VERSION 5.7 ;
  NOWIREEXTENSIONATPIN ON ;
  DIVIDERCHAR "/" ;
  BUSBITCHARS "[]" ;
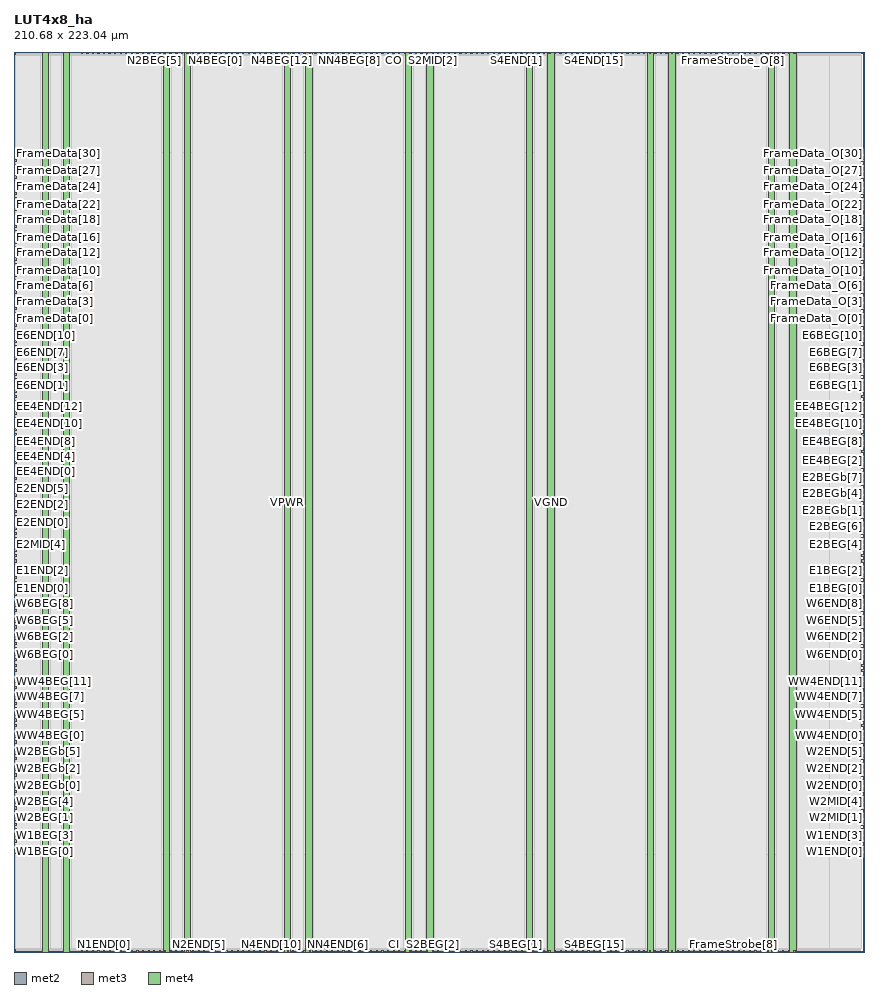
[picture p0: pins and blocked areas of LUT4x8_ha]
MACRO LUT4x8_ha
  CLASS BLOCK ;
  FOREIGN LUT4x8_ha ;
  ORIGIN 0.000 0.000 ;
  SIZE 210.680 BY 223.040 ;
  PIN CI
    DIRECTION INPUT ;
    USE SIGNAL ;
    ANTENNAGATEAREA 0.499500 ;
    PORT
      LAYER met2 ;
        RECT 93.930 0.000 94.210 0.280 ;
    END
  END CI
  PIN CO
    DIRECTION OUTPUT ;
    USE SIGNAL ;
    ANTENNADIFFAREA 0.702900 ;
    PORT
      LAYER met2 ;
        RECT 93.930 222.760 94.210 223.040 ;
    END
  END CO
  PIN E1BEG[0]
    DIRECTION OUTPUT ;
    USE SIGNAL ;
    ANTENNADIFFAREA 0.702900 ;
    PORT
      LAYER met3 ;
        RECT 210.080 89.800 210.680 90.400 ;
    END
  END E1BEG[0]
  PIN E1BEG[1]
    DIRECTION OUTPUT ;
    USE SIGNAL ;
    ANTENNADIFFAREA 0.702900 ;
    PORT
      LAYER met3 ;
        RECT 210.080 91.160 210.680 91.760 ;
    END
  END E1BEG[1]
  PIN E1BEG[2]
    DIRECTION OUTPUT ;
    USE SIGNAL ;
    ANTENNADIFFAREA 0.702900 ;
    PORT
      LAYER met3 ;
        RECT 210.080 92.520 210.680 93.120 ;
    END
  END E1BEG[2]
  PIN E1BEG[3]
    DIRECTION OUTPUT ;
    USE SIGNAL ;
    ANTENNADIFFAREA 0.702900 ;
    PORT
      LAYER met3 ;
        RECT 210.080 93.880 210.680 94.480 ;
    END
  END E1BEG[3]
  PIN E1END[0]
    DIRECTION INPUT ;
    USE SIGNAL ;
    ANTENNAGATEAREA 2.912100 ;
    ANTENNADIFFAREA 1.304100 ;
    PORT
      LAYER met3 ;
        RECT 0.000 89.800 0.600 90.400 ;
    END
  END E1END[0]
  PIN E1END[1]
    DIRECTION INPUT ;
    USE SIGNAL ;
    ANTENNAGATEAREA 1.431000 ;
    PORT
      LAYER met3 ;
        RECT 0.000 91.160 0.600 91.760 ;
    END
  END E1END[1]
  PIN E1END[2]
    DIRECTION INPUT ;
    USE SIGNAL ;
    ANTENNAGATEAREA 1.749000 ;
    PORT
      LAYER met3 ;
        RECT 0.000 92.520 0.600 93.120 ;
    END
  END E1END[2]
  PIN E1END[3]
    DIRECTION INPUT ;
    USE SIGNAL ;
    ANTENNAGATEAREA 2.618400 ;
    ANTENNADIFFAREA 0.869400 ;
    PORT
      LAYER met3 ;
        RECT 0.000 93.880 0.600 94.480 ;
    END
  END E1END[3]
  PIN E2BEG[0]
    DIRECTION OUTPUT ;
    USE SIGNAL ;
    ANTENNADIFFAREA 0.702900 ;
    PORT
      LAYER met3 ;
        RECT 210.080 95.240 210.680 95.840 ;
    END
  END E2BEG[0]
  PIN E2BEG[1]
    DIRECTION OUTPUT ;
    USE SIGNAL ;
    ANTENNADIFFAREA 0.702900 ;
    PORT
      LAYER met3 ;
        RECT 210.080 96.600 210.680 97.200 ;
    END
  END E2BEG[1]
  PIN E2BEG[2]
    DIRECTION OUTPUT ;
    USE SIGNAL ;
    ANTENNADIFFAREA 0.702900 ;
    PORT
      LAYER met3 ;
        RECT 210.080 97.960 210.680 98.560 ;
    END
  END E2BEG[2]
  PIN E2BEG[3]
    DIRECTION OUTPUT ;
    USE SIGNAL ;
    ANTENNADIFFAREA 0.702900 ;
    PORT
      LAYER met3 ;
        RECT 210.080 99.320 210.680 99.920 ;
    END
  END E2BEG[3]
  PIN E2BEG[4]
    DIRECTION OUTPUT ;
    USE SIGNAL ;
    ANTENNADIFFAREA 0.702900 ;
    PORT
      LAYER met3 ;
        RECT 210.080 100.680 210.680 101.280 ;
    END
  END E2BEG[4]
  PIN E2BEG[5]
    DIRECTION OUTPUT ;
    USE SIGNAL ;
    ANTENNADIFFAREA 0.702900 ;
    PORT
      LAYER met3 ;
        RECT 210.080 102.040 210.680 102.640 ;
    END
  END E2BEG[5]
  PIN E2BEG[6]
    DIRECTION OUTPUT ;
    USE SIGNAL ;
    ANTENNADIFFAREA 0.702900 ;
    PORT
      LAYER met3 ;
        RECT 210.080 103.400 210.680 104.000 ;
    END
  END E2BEG[6]
  PIN E2BEG[7]
    DIRECTION OUTPUT ;
    USE SIGNAL ;
    ANTENNADIFFAREA 0.702900 ;
    PORT
      LAYER met3 ;
        RECT 210.080 104.760 210.680 105.360 ;
    END
  END E2BEG[7]
  PIN E2BEGb[0]
    DIRECTION OUTPUT ;
    USE SIGNAL ;
    ANTENNADIFFAREA 0.702900 ;
    PORT
      LAYER met3 ;
        RECT 210.080 106.120 210.680 106.720 ;
    END
  END E2BEGb[0]
  PIN E2BEGb[1]
    DIRECTION OUTPUT ;
    USE SIGNAL ;
    ANTENNADIFFAREA 0.702900 ;
    PORT
      LAYER met3 ;
        RECT 210.080 107.480 210.680 108.080 ;
    END
  END E2BEGb[1]
  PIN E2BEGb[2]
    DIRECTION OUTPUT ;
    USE SIGNAL ;
    ANTENNADIFFAREA 0.702900 ;
    PORT
      LAYER met3 ;
        RECT 210.080 108.840 210.680 109.440 ;
    END
  END E2BEGb[2]
  PIN E2BEGb[3]
    DIRECTION OUTPUT ;
    USE SIGNAL ;
    ANTENNADIFFAREA 0.702900 ;
    PORT
      LAYER met3 ;
        RECT 210.080 110.200 210.680 110.800 ;
    END
  END E2BEGb[3]
  PIN E2BEGb[4]
    DIRECTION OUTPUT ;
    USE SIGNAL ;
    ANTENNADIFFAREA 0.702900 ;
    PORT
      LAYER met3 ;
        RECT 210.080 111.560 210.680 112.160 ;
    END
  END E2BEGb[4]
  PIN E2BEGb[5]
    DIRECTION OUTPUT ;
    USE SIGNAL ;
    ANTENNADIFFAREA 0.702900 ;
    PORT
      LAYER met3 ;
        RECT 210.080 112.920 210.680 113.520 ;
    END
  END E2BEGb[5]
  PIN E2BEGb[6]
    DIRECTION OUTPUT ;
    USE SIGNAL ;
    ANTENNADIFFAREA 0.702900 ;
    PORT
      LAYER met3 ;
        RECT 210.080 114.280 210.680 114.880 ;
    END
  END E2BEGb[6]
  PIN E2BEGb[7]
    DIRECTION OUTPUT ;
    USE SIGNAL ;
    ANTENNADIFFAREA 0.702900 ;
    PORT
      LAYER met3 ;
        RECT 210.080 115.640 210.680 116.240 ;
    END
  END E2BEGb[7]
  PIN E2END[0]
    DIRECTION INPUT ;
    USE SIGNAL ;
    ANTENNAGATEAREA 0.636000 ;
    PORT
      LAYER met3 ;
        RECT 0.000 106.120 0.600 106.720 ;
    END
  END E2END[0]
  PIN E2END[1]
    DIRECTION INPUT ;
    USE SIGNAL ;
    ANTENNAGATEAREA 1.070700 ;
    ANTENNADIFFAREA 0.434700 ;
    PORT
      LAYER met3 ;
        RECT 0.000 107.480 0.600 108.080 ;
    END
  END E2END[1]
  PIN E2END[2]
    DIRECTION INPUT ;
    USE SIGNAL ;
    ANTENNAGATEAREA 1.113000 ;
    PORT
      LAYER met3 ;
        RECT 0.000 108.840 0.600 109.440 ;
    END
  END E2END[2]
  PIN E2END[3]
    DIRECTION INPUT ;
    USE SIGNAL ;
    ANTENNAGATEAREA 1.113000 ;
    PORT
      LAYER met3 ;
        RECT 0.000 110.200 0.600 110.800 ;
    END
  END E2END[3]
  PIN E2END[4]
    DIRECTION INPUT ;
    USE SIGNAL ;
    ANTENNAGATEAREA 0.795000 ;
    PORT
      LAYER met3 ;
        RECT 0.000 111.560 0.600 112.160 ;
    END
  END E2END[4]
  PIN E2END[5]
    DIRECTION INPUT ;
    USE SIGNAL ;
    ANTENNAGATEAREA 0.954000 ;
    PORT
      LAYER met3 ;
        RECT 0.000 112.920 0.600 113.520 ;
    END
  END E2END[5]
  PIN E2END[6]
    DIRECTION INPUT ;
    USE SIGNAL ;
    ANTENNAGATEAREA 0.954000 ;
    PORT
      LAYER met3 ;
        RECT 0.000 114.280 0.600 114.880 ;
    END
  END E2END[6]
  PIN E2END[7]
    DIRECTION INPUT ;
    USE SIGNAL ;
    ANTENNAGATEAREA 0.795000 ;
    PORT
      LAYER met3 ;
        RECT 0.000 115.640 0.600 116.240 ;
    END
  END E2END[7]
  PIN E2MID[0]
    DIRECTION INPUT ;
    USE SIGNAL ;
    ANTENNAGATEAREA 0.636000 ;
    PORT
      LAYER met3 ;
        RECT 0.000 95.240 0.600 95.840 ;
    END
  END E2MID[0]
  PIN E2MID[1]
    DIRECTION INPUT ;
    USE SIGNAL ;
    ANTENNAGATEAREA 0.795000 ;
    PORT
      LAYER met3 ;
        RECT 0.000 96.600 0.600 97.200 ;
    END
  END E2MID[1]
  PIN E2MID[2]
    DIRECTION INPUT ;
    USE SIGNAL ;
    ANTENNAGATEAREA 2.374800 ;
    ANTENNADIFFAREA 1.738800 ;
    PORT
      LAYER met3 ;
        RECT 0.000 97.960 0.600 98.560 ;
    END
  END E2MID[2]
  PIN E2MID[3]
    DIRECTION INPUT ;
    USE SIGNAL ;
    ANTENNAGATEAREA 1.664400 ;
    ANTENNADIFFAREA 0.869400 ;
    PORT
      LAYER met3 ;
        RECT 0.000 99.320 0.600 99.920 ;
    END
  END E2MID[3]
  PIN E2MID[4]
    DIRECTION INPUT ;
    USE SIGNAL ;
    ANTENNAGATEAREA 1.196700 ;
    ANTENNADIFFAREA 0.434700 ;
    PORT
      LAYER met3 ;
        RECT 0.000 100.680 0.600 101.280 ;
    END
  END E2MID[4]
  PIN E2MID[5]
    DIRECTION INPUT ;
    USE SIGNAL ;
    ANTENNAGATEAREA 0.795000 ;
    PORT
      LAYER met3 ;
        RECT 0.000 102.040 0.600 102.640 ;
    END
  END E2MID[5]
  PIN E2MID[6]
    DIRECTION INPUT ;
    USE SIGNAL ;
    ANTENNAGATEAREA 1.940100 ;
    ANTENNADIFFAREA 1.304100 ;
    PORT
      LAYER met3 ;
        RECT 0.000 103.400 0.600 104.000 ;
    END
  END E2MID[6]
  PIN E2MID[7]
    DIRECTION INPUT ;
    USE SIGNAL ;
    ANTENNAGATEAREA 0.795000 ;
    PORT
      LAYER met3 ;
        RECT 0.000 104.760 0.600 105.360 ;
    END
  END E2MID[7]
  PIN E6BEG[0]
    DIRECTION OUTPUT ;
    USE SIGNAL ;
    ANTENNADIFFAREA 0.702900 ;
    PORT
      LAYER met3 ;
        RECT 210.080 138.760 210.680 139.360 ;
    END
  END E6BEG[0]
  PIN E6BEG[10]
    DIRECTION OUTPUT ;
    USE SIGNAL ;
    ANTENNADIFFAREA 0.702900 ;
    PORT
      LAYER met3 ;
        RECT 210.080 152.360 210.680 152.960 ;
    END
  END E6BEG[10]
  PIN E6BEG[11]
    DIRECTION OUTPUT ;
    USE SIGNAL ;
    ANTENNADIFFAREA 0.702900 ;
    PORT
      LAYER met3 ;
        RECT 210.080 153.720 210.680 154.320 ;
    END
  END E6BEG[11]
  PIN E6BEG[1]
    DIRECTION OUTPUT ;
    USE SIGNAL ;
    ANTENNADIFFAREA 0.702900 ;
    PORT
      LAYER met3 ;
        RECT 210.080 140.120 210.680 140.720 ;
    END
  END E6BEG[1]
  PIN E6BEG[2]
    DIRECTION OUTPUT ;
    USE SIGNAL ;
    ANTENNADIFFAREA 0.702900 ;
    PORT
      LAYER met3 ;
        RECT 210.080 141.480 210.680 142.080 ;
    END
  END E6BEG[2]
  PIN E6BEG[3]
    DIRECTION OUTPUT ;
    USE SIGNAL ;
    ANTENNADIFFAREA 0.702900 ;
    PORT
      LAYER met3 ;
        RECT 210.080 142.840 210.680 143.440 ;
    END
  END E6BEG[3]
  PIN E6BEG[4]
    DIRECTION OUTPUT ;
    USE SIGNAL ;
    ANTENNADIFFAREA 0.702900 ;
    PORT
      LAYER met3 ;
        RECT 210.080 144.200 210.680 144.800 ;
    END
  END E6BEG[4]
  PIN E6BEG[5]
    DIRECTION OUTPUT ;
    USE SIGNAL ;
    ANTENNADIFFAREA 0.702900 ;
    PORT
      LAYER met3 ;
        RECT 210.080 145.560 210.680 146.160 ;
    END
  END E6BEG[5]
  PIN E6BEG[6]
    DIRECTION OUTPUT ;
    USE SIGNAL ;
    ANTENNADIFFAREA 0.702900 ;
    PORT
      LAYER met3 ;
        RECT 210.080 146.920 210.680 147.520 ;
    END
  END E6BEG[6]
  PIN E6BEG[7]
    DIRECTION OUTPUT ;
    USE SIGNAL ;
    ANTENNADIFFAREA 0.702900 ;
    PORT
      LAYER met3 ;
        RECT 210.080 148.280 210.680 148.880 ;
    END
  END E6BEG[7]
  PIN E6BEG[8]
    DIRECTION OUTPUT ;
    USE SIGNAL ;
    ANTENNADIFFAREA 0.702900 ;
    PORT
      LAYER met3 ;
        RECT 210.080 149.640 210.680 150.240 ;
    END
  END E6BEG[8]
  PIN E6BEG[9]
    DIRECTION OUTPUT ;
    USE SIGNAL ;
    ANTENNADIFFAREA 0.702900 ;
    PORT
      LAYER met3 ;
        RECT 210.080 151.000 210.680 151.600 ;
    END
  END E6BEG[9]
  PIN E6END[0]
    DIRECTION INPUT ;
    USE SIGNAL ;
    ANTENNAGATEAREA 1.908000 ;
    PORT
      LAYER met3 ;
        RECT 0.000 138.760 0.600 139.360 ;
    END
  END E6END[0]
  PIN E6END[10]
    DIRECTION INPUT ;
    USE SIGNAL ;
    ANTENNAGATEAREA 0.159000 ;
    PORT
      LAYER met3 ;
        RECT 0.000 152.360 0.600 152.960 ;
    END
  END E6END[10]
  PIN E6END[11]
    DIRECTION INPUT ;
    USE SIGNAL ;
    ANTENNAGATEAREA 0.159000 ;
    PORT
      LAYER met3 ;
        RECT 0.000 153.720 0.600 154.320 ;
    END
  END E6END[11]
  PIN E6END[1]
    DIRECTION INPUT ;
    USE SIGNAL ;
    ANTENNAGATEAREA 3.646800 ;
    ANTENNADIFFAREA 1.738800 ;
    PORT
      LAYER met3 ;
        RECT 0.000 140.120 0.600 140.720 ;
    END
  END E6END[1]
  PIN E6END[2]
    DIRECTION INPUT ;
    USE SIGNAL ;
    ANTENNAGATEAREA 0.159000 ;
    PORT
      LAYER met3 ;
        RECT 0.000 141.480 0.600 142.080 ;
    END
  END E6END[2]
  PIN E6END[3]
    DIRECTION INPUT ;
    USE SIGNAL ;
    ANTENNAGATEAREA 0.159000 ;
    PORT
      LAYER met3 ;
        RECT 0.000 142.840 0.600 143.440 ;
    END
  END E6END[3]
  PIN E6END[4]
    DIRECTION INPUT ;
    USE SIGNAL ;
    ANTENNAGATEAREA 0.159000 ;
    PORT
      LAYER met3 ;
        RECT 0.000 144.200 0.600 144.800 ;
    END
  END E6END[4]
  PIN E6END[5]
    DIRECTION INPUT ;
    USE SIGNAL ;
    ANTENNAGATEAREA 0.159000 ;
    PORT
      LAYER met3 ;
        RECT 0.000 145.560 0.600 146.160 ;
    END
  END E6END[5]
  PIN E6END[6]
    DIRECTION INPUT ;
    USE SIGNAL ;
    ANTENNAGATEAREA 0.159000 ;
    PORT
      LAYER met3 ;
        RECT 0.000 146.920 0.600 147.520 ;
    END
  END E6END[6]
  PIN E6END[7]
    DIRECTION INPUT ;
    USE SIGNAL ;
    ANTENNAGATEAREA 0.159000 ;
    PORT
      LAYER met3 ;
        RECT 0.000 148.280 0.600 148.880 ;
    END
  END E6END[7]
  PIN E6END[8]
    DIRECTION INPUT ;
    USE SIGNAL ;
    ANTENNAGATEAREA 0.159000 ;
    PORT
      LAYER met3 ;
        RECT 0.000 149.640 0.600 150.240 ;
    END
  END E6END[8]
  PIN E6END[9]
    DIRECTION INPUT ;
    USE SIGNAL ;
    ANTENNAGATEAREA 0.159000 ;
    PORT
      LAYER met3 ;
        RECT 0.000 151.000 0.600 151.600 ;
    END
  END E6END[9]
  PIN EE4BEG[0]
    DIRECTION OUTPUT ;
    USE SIGNAL ;
    ANTENNADIFFAREA 0.702900 ;
    PORT
      LAYER met3 ;
        RECT 210.080 117.000 210.680 117.600 ;
    END
  END EE4BEG[0]
  PIN EE4BEG[10]
    DIRECTION OUTPUT ;
    USE SIGNAL ;
    ANTENNADIFFAREA 0.702900 ;
    PORT
      LAYER met3 ;
        RECT 210.080 130.600 210.680 131.200 ;
    END
  END EE4BEG[10]
  PIN EE4BEG[11]
    DIRECTION OUTPUT ;
    USE SIGNAL ;
    ANTENNADIFFAREA 0.702900 ;
    PORT
      LAYER met3 ;
        RECT 210.080 131.960 210.680 132.560 ;
    END
  END EE4BEG[11]
  PIN EE4BEG[12]
    DIRECTION OUTPUT ;
    USE SIGNAL ;
    ANTENNADIFFAREA 0.702900 ;
    PORT
      LAYER met3 ;
        RECT 210.080 133.320 210.680 133.920 ;
    END
  END EE4BEG[12]
  PIN EE4BEG[13]
    DIRECTION OUTPUT ;
    USE SIGNAL ;
    ANTENNADIFFAREA 0.702900 ;
    PORT
      LAYER met3 ;
        RECT 210.080 134.680 210.680 135.280 ;
    END
  END EE4BEG[13]
  PIN EE4BEG[14]
    DIRECTION OUTPUT ;
    USE SIGNAL ;
    ANTENNADIFFAREA 0.702900 ;
    PORT
      LAYER met3 ;
        RECT 210.080 136.040 210.680 136.640 ;
    END
  END EE4BEG[14]
  PIN EE4BEG[15]
    DIRECTION OUTPUT ;
    USE SIGNAL ;
    ANTENNADIFFAREA 0.702900 ;
    PORT
      LAYER met3 ;
        RECT 210.080 137.400 210.680 138.000 ;
    END
  END EE4BEG[15]
  PIN EE4BEG[1]
    DIRECTION OUTPUT ;
    USE SIGNAL ;
    ANTENNADIFFAREA 0.702900 ;
    PORT
      LAYER met3 ;
        RECT 210.080 118.360 210.680 118.960 ;
    END
  END EE4BEG[1]
  PIN EE4BEG[2]
    DIRECTION OUTPUT ;
    USE SIGNAL ;
    ANTENNADIFFAREA 0.702900 ;
    PORT
      LAYER met3 ;
        RECT 210.080 119.720 210.680 120.320 ;
    END
  END EE4BEG[2]
  PIN EE4BEG[3]
    DIRECTION OUTPUT ;
    USE SIGNAL ;
    ANTENNADIFFAREA 0.702900 ;
    PORT
      LAYER met3 ;
        RECT 210.080 121.080 210.680 121.680 ;
    END
  END EE4BEG[3]
  PIN EE4BEG[4]
    DIRECTION OUTPUT ;
    USE SIGNAL ;
    ANTENNADIFFAREA 0.702900 ;
    PORT
      LAYER met3 ;
        RECT 210.080 122.440 210.680 123.040 ;
    END
  END EE4BEG[4]
  PIN EE4BEG[5]
    DIRECTION OUTPUT ;
    USE SIGNAL ;
    ANTENNADIFFAREA 0.702900 ;
    PORT
      LAYER met3 ;
        RECT 210.080 123.800 210.680 124.400 ;
    END
  END EE4BEG[5]
  PIN EE4BEG[6]
    DIRECTION OUTPUT ;
    USE SIGNAL ;
    ANTENNADIFFAREA 0.702900 ;
    PORT
      LAYER met3 ;
        RECT 210.080 125.160 210.680 125.760 ;
    END
  END EE4BEG[6]
  PIN EE4BEG[7]
    DIRECTION OUTPUT ;
    USE SIGNAL ;
    ANTENNADIFFAREA 0.702900 ;
    PORT
      LAYER met3 ;
        RECT 210.080 126.520 210.680 127.120 ;
    END
  END EE4BEG[7]
  PIN EE4BEG[8]
    DIRECTION OUTPUT ;
    USE SIGNAL ;
    ANTENNADIFFAREA 0.702900 ;
    PORT
      LAYER met3 ;
        RECT 210.080 127.880 210.680 128.480 ;
    END
  END EE4BEG[8]
  PIN EE4BEG[9]
    DIRECTION OUTPUT ;
    USE SIGNAL ;
    ANTENNADIFFAREA 0.702900 ;
    PORT
      LAYER met3 ;
        RECT 210.080 129.240 210.680 129.840 ;
    END
  END EE4BEG[9]
  PIN EE4END[0]
    DIRECTION INPUT ;
    USE SIGNAL ;
    ANTENNAGATEAREA 0.911700 ;
    ANTENNADIFFAREA 0.434700 ;
    PORT
      LAYER met3 ;
        RECT 0.000 117.000 0.600 117.600 ;
    END
  END EE4END[0]
  PIN EE4END[10]
    DIRECTION INPUT ;
    USE SIGNAL ;
    ANTENNAGATEAREA 0.159000 ;
    PORT
      LAYER met3 ;
        RECT 0.000 130.600 0.600 131.200 ;
    END
  END EE4END[10]
  PIN EE4END[11]
    DIRECTION INPUT ;
    USE SIGNAL ;
    ANTENNAGATEAREA 0.159000 ;
    PORT
      LAYER met3 ;
        RECT 0.000 131.960 0.600 132.560 ;
    END
  END EE4END[11]
  PIN EE4END[12]
    DIRECTION INPUT ;
    USE SIGNAL ;
    ANTENNAGATEAREA 0.159000 ;
    PORT
      LAYER met3 ;
        RECT 0.000 133.320 0.600 133.920 ;
    END
  END EE4END[12]
  PIN EE4END[13]
    DIRECTION INPUT ;
    USE SIGNAL ;
    ANTENNAGATEAREA 0.159000 ;
    PORT
      LAYER met3 ;
        RECT 0.000 134.680 0.600 135.280 ;
    END
  END EE4END[13]
  PIN EE4END[14]
    DIRECTION INPUT ;
    USE SIGNAL ;
    ANTENNAGATEAREA 0.159000 ;
    PORT
      LAYER met3 ;
        RECT 0.000 136.040 0.600 136.640 ;
    END
  END EE4END[14]
  PIN EE4END[15]
    DIRECTION INPUT ;
    USE SIGNAL ;
    ANTENNAGATEAREA 0.159000 ;
    PORT
      LAYER met3 ;
        RECT 0.000 137.400 0.600 138.000 ;
    END
  END EE4END[15]
  PIN EE4END[1]
    DIRECTION INPUT ;
    USE SIGNAL ;
    ANTENNAGATEAREA 1.346400 ;
    ANTENNADIFFAREA 0.869400 ;
    PORT
      LAYER met3 ;
        RECT 0.000 118.360 0.600 118.960 ;
    END
  END EE4END[1]
  PIN EE4END[2]
    DIRECTION INPUT ;
    USE SIGNAL ;
    ANTENNAGATEAREA 1.346400 ;
    ANTENNADIFFAREA 0.869400 ;
    PORT
      LAYER met3 ;
        RECT 0.000 119.720 0.600 120.320 ;
    END
  END EE4END[2]
  PIN EE4END[3]
    DIRECTION INPUT ;
    USE SIGNAL ;
    ANTENNAGATEAREA 0.477000 ;
    PORT
      LAYER met3 ;
        RECT 0.000 121.080 0.600 121.680 ;
    END
  END EE4END[3]
  PIN EE4END[4]
    DIRECTION INPUT ;
    USE SIGNAL ;
    ANTENNAGATEAREA 0.159000 ;
    PORT
      LAYER met3 ;
        RECT 0.000 122.440 0.600 123.040 ;
    END
  END EE4END[4]
  PIN EE4END[5]
    DIRECTION INPUT ;
    USE SIGNAL ;
    ANTENNAGATEAREA 0.159000 ;
    PORT
      LAYER met3 ;
        RECT 0.000 123.800 0.600 124.400 ;
    END
  END EE4END[5]
  PIN EE4END[6]
    DIRECTION INPUT ;
    USE SIGNAL ;
    ANTENNAGATEAREA 0.159000 ;
    PORT
      LAYER met3 ;
        RECT 0.000 125.160 0.600 125.760 ;
    END
  END EE4END[6]
  PIN EE4END[7]
    DIRECTION INPUT ;
    USE SIGNAL ;
    ANTENNAGATEAREA 0.159000 ;
    PORT
      LAYER met3 ;
        RECT 0.000 126.520 0.600 127.120 ;
    END
  END EE4END[7]
  PIN EE4END[8]
    DIRECTION INPUT ;
    USE SIGNAL ;
    ANTENNAGATEAREA 0.159000 ;
    PORT
      LAYER met3 ;
        RECT 0.000 127.880 0.600 128.480 ;
    END
  END EE4END[8]
  PIN EE4END[9]
    DIRECTION INPUT ;
    USE SIGNAL ;
    ANTENNAGATEAREA 0.159000 ;
    PORT
      LAYER met3 ;
        RECT 0.000 129.240 0.600 129.840 ;
    END
  END EE4END[9]
  PIN FrameData[0]
    DIRECTION INPUT ;
    USE SIGNAL ;
    ANTENNAGATEAREA 4.918800 ;
    ANTENNADIFFAREA 1.738800 ;
    PORT
      LAYER met3 ;
        RECT 0.000 155.080 0.600 155.680 ;
    END
  END FrameData[0]
  PIN FrameData[10]
    DIRECTION INPUT ;
    USE SIGNAL ;
    ANTENNAGATEAREA 3.180000 ;
    PORT
      LAYER met3 ;
        RECT 0.000 168.680 0.600 169.280 ;
    END
  END FrameData[10]
  PIN FrameData[11]
    DIRECTION INPUT ;
    USE SIGNAL ;
    ANTENNAGATEAREA 3.180000 ;
    PORT
      LAYER met3 ;
        RECT 0.000 170.040 0.600 170.640 ;
    END
  END FrameData[11]
  PIN FrameData[12]
    DIRECTION INPUT ;
    USE SIGNAL ;
    ANTENNAGATEAREA 3.180000 ;
    PORT
      LAYER met3 ;
        RECT 0.000 171.400 0.600 172.000 ;
    END
  END FrameData[12]
  PIN FrameData[13]
    DIRECTION INPUT ;
    USE SIGNAL ;
    ANTENNAGATEAREA 3.180000 ;
    PORT
      LAYER met3 ;
        RECT 0.000 172.760 0.600 173.360 ;
    END
  END FrameData[13]
  PIN FrameData[14]
    DIRECTION INPUT ;
    USE SIGNAL ;
    ANTENNAGATEAREA 3.180000 ;
    PORT
      LAYER met3 ;
        RECT 0.000 174.120 0.600 174.720 ;
    END
  END FrameData[14]
  PIN FrameData[15]
    DIRECTION INPUT ;
    USE SIGNAL ;
    ANTENNAGATEAREA 3.180000 ;
    PORT
      LAYER met3 ;
        RECT 0.000 175.480 0.600 176.080 ;
    END
  END FrameData[15]
  PIN FrameData[16]
    DIRECTION INPUT ;
    USE SIGNAL ;
    ANTENNAGATEAREA 3.180000 ;
    PORT
      LAYER met3 ;
        RECT 0.000 176.840 0.600 177.440 ;
    END
  END FrameData[16]
  PIN FrameData[17]
    DIRECTION INPUT ;
    USE SIGNAL ;
    ANTENNAGATEAREA 3.180000 ;
    PORT
      LAYER met3 ;
        RECT 0.000 178.200 0.600 178.800 ;
    END
  END FrameData[17]
  PIN FrameData[18]
    DIRECTION INPUT ;
    USE SIGNAL ;
    ANTENNAGATEAREA 3.180000 ;
    PORT
      LAYER met3 ;
        RECT 0.000 179.560 0.600 180.160 ;
    END
  END FrameData[18]
  PIN FrameData[19]
    DIRECTION INPUT ;
    USE SIGNAL ;
    ANTENNAGATEAREA 3.180000 ;
    PORT
      LAYER met3 ;
        RECT 0.000 180.920 0.600 181.520 ;
    END
  END FrameData[19]
  PIN FrameData[1]
    DIRECTION INPUT ;
    USE SIGNAL ;
    ANTENNAGATEAREA 4.049400 ;
    ANTENNADIFFAREA 0.869400 ;
    PORT
      LAYER met3 ;
        RECT 0.000 156.440 0.600 157.040 ;
    END
  END FrameData[1]
  PIN FrameData[20]
    DIRECTION INPUT ;
    USE SIGNAL ;
    ANTENNAGATEAREA 4.049400 ;
    ANTENNADIFFAREA 0.869400 ;
    PORT
      LAYER met3 ;
        RECT 0.000 182.280 0.600 182.880 ;
    END
  END FrameData[20]
  PIN FrameData[21]
    DIRECTION INPUT ;
    USE SIGNAL ;
    ANTENNAGATEAREA 3.180000 ;
    PORT
      LAYER met3 ;
        RECT 0.000 183.640 0.600 184.240 ;
    END
  END FrameData[21]
  PIN FrameData[22]
    DIRECTION INPUT ;
    USE SIGNAL ;
    ANTENNAGATEAREA 3.180000 ;
    PORT
      LAYER met3 ;
        RECT 0.000 185.000 0.600 185.600 ;
    END
  END FrameData[22]
  PIN FrameData[23]
    DIRECTION INPUT ;
    USE SIGNAL ;
    ANTENNAGATEAREA 3.180000 ;
    PORT
      LAYER met3 ;
        RECT 0.000 186.360 0.600 186.960 ;
    END
  END FrameData[23]
  PIN FrameData[24]
    DIRECTION INPUT ;
    USE SIGNAL ;
    ANTENNAGATEAREA 3.614700 ;
    ANTENNADIFFAREA 0.434700 ;
    PORT
      LAYER met3 ;
        RECT 0.000 187.720 0.600 188.320 ;
    END
  END FrameData[24]
  PIN FrameData[25]
    DIRECTION INPUT ;
    USE SIGNAL ;
    ANTENNAGATEAREA 3.180000 ;
    PORT
      LAYER met3 ;
        RECT 0.000 189.080 0.600 189.680 ;
    END
  END FrameData[25]
  PIN FrameData[26]
    DIRECTION INPUT ;
    USE SIGNAL ;
    ANTENNAGATEAREA 3.339000 ;
    PORT
      LAYER met3 ;
        RECT 0.000 190.440 0.600 191.040 ;
    END
  END FrameData[26]
  PIN FrameData[27]
    DIRECTION INPUT ;
    USE SIGNAL ;
    ANTENNAGATEAREA 3.339000 ;
    PORT
      LAYER met3 ;
        RECT 0.000 191.800 0.600 192.400 ;
    END
  END FrameData[27]
  PIN FrameData[28]
    DIRECTION INPUT ;
    USE SIGNAL ;
    ANTENNAGATEAREA 3.339000 ;
    PORT
      LAYER met3 ;
        RECT 0.000 193.160 0.600 193.760 ;
    END
  END FrameData[28]
  PIN FrameData[29]
    DIRECTION INPUT ;
    USE SIGNAL ;
    ANTENNAGATEAREA 3.339000 ;
    PORT
      LAYER met3 ;
        RECT 0.000 194.520 0.600 195.120 ;
    END
  END FrameData[29]
  PIN FrameData[2]
    DIRECTION INPUT ;
    USE SIGNAL ;
    ANTENNAGATEAREA 3.180000 ;
    PORT
      LAYER met3 ;
        RECT 0.000 157.800 0.600 158.400 ;
    END
  END FrameData[2]
  PIN FrameData[30]
    DIRECTION INPUT ;
    USE SIGNAL ;
    ANTENNAGATEAREA 3.339000 ;
    PORT
      LAYER met3 ;
        RECT 0.000 195.880 0.600 196.480 ;
    END
  END FrameData[30]
  PIN FrameData[31]
    DIRECTION INPUT ;
    USE SIGNAL ;
    ANTENNAGATEAREA 3.339000 ;
    PORT
      LAYER met3 ;
        RECT 0.000 197.240 0.600 197.840 ;
    END
  END FrameData[31]
  PIN FrameData[3]
    DIRECTION INPUT ;
    USE SIGNAL ;
    ANTENNAGATEAREA 4.049400 ;
    ANTENNADIFFAREA 0.869400 ;
    PORT
      LAYER met3 ;
        RECT 0.000 159.160 0.600 159.760 ;
    END
  END FrameData[3]
  PIN FrameData[4]
    DIRECTION INPUT ;
    USE SIGNAL ;
    ANTENNAGATEAREA 3.180000 ;
    PORT
      LAYER met3 ;
        RECT 0.000 160.520 0.600 161.120 ;
    END
  END FrameData[4]
  PIN FrameData[5]
    DIRECTION INPUT ;
    USE SIGNAL ;
    ANTENNAGATEAREA 3.180000 ;
    PORT
      LAYER met3 ;
        RECT 0.000 161.880 0.600 162.480 ;
    END
  END FrameData[5]
  PIN FrameData[6]
    DIRECTION INPUT ;
    USE SIGNAL ;
    ANTENNAGATEAREA 3.180000 ;
    PORT
      LAYER met3 ;
        RECT 0.000 163.240 0.600 163.840 ;
    END
  END FrameData[6]
  PIN FrameData[7]
    DIRECTION INPUT ;
    USE SIGNAL ;
    ANTENNAGATEAREA 4.918800 ;
    ANTENNADIFFAREA 1.738800 ;
    PORT
      LAYER met3 ;
        RECT 0.000 164.600 0.600 165.200 ;
    END
  END FrameData[7]
  PIN FrameData[8]
    DIRECTION INPUT ;
    USE SIGNAL ;
    ANTENNAGATEAREA 3.180000 ;
    PORT
      LAYER met3 ;
        RECT 0.000 165.960 0.600 166.560 ;
    END
  END FrameData[8]
  PIN FrameData[9]
    DIRECTION INPUT ;
    USE SIGNAL ;
    ANTENNAGATEAREA 3.614700 ;
    ANTENNADIFFAREA 0.434700 ;
    PORT
      LAYER met3 ;
        RECT 0.000 167.320 0.600 167.920 ;
    END
  END FrameData[9]
  PIN FrameData_O[0]
    DIRECTION OUTPUT ;
    USE SIGNAL ;
    ANTENNADIFFAREA 0.702900 ;
    PORT
      LAYER met3 ;
        RECT 210.080 155.080 210.680 155.680 ;
    END
  END FrameData_O[0]
  PIN FrameData_O[10]
    DIRECTION OUTPUT ;
    USE SIGNAL ;
    ANTENNADIFFAREA 0.702900 ;
    PORT
      LAYER met3 ;
        RECT 210.080 168.680 210.680 169.280 ;
    END
  END FrameData_O[10]
  PIN FrameData_O[11]
    DIRECTION OUTPUT ;
    USE SIGNAL ;
    ANTENNADIFFAREA 0.702900 ;
    PORT
      LAYER met3 ;
        RECT 210.080 170.040 210.680 170.640 ;
    END
  END FrameData_O[11]
  PIN FrameData_O[12]
    DIRECTION OUTPUT ;
    USE SIGNAL ;
    ANTENNADIFFAREA 0.702900 ;
    PORT
      LAYER met3 ;
        RECT 210.080 171.400 210.680 172.000 ;
    END
  END FrameData_O[12]
  PIN FrameData_O[13]
    DIRECTION OUTPUT ;
    USE SIGNAL ;
    ANTENNADIFFAREA 0.702900 ;
    PORT
      LAYER met3 ;
        RECT 210.080 172.760 210.680 173.360 ;
    END
  END FrameData_O[13]
  PIN FrameData_O[14]
    DIRECTION OUTPUT ;
    USE SIGNAL ;
    ANTENNADIFFAREA 0.702900 ;
    PORT
      LAYER met3 ;
        RECT 210.080 174.120 210.680 174.720 ;
    END
  END FrameData_O[14]
  PIN FrameData_O[15]
    DIRECTION OUTPUT ;
    USE SIGNAL ;
    ANTENNADIFFAREA 0.702900 ;
    PORT
      LAYER met3 ;
        RECT 210.080 175.480 210.680 176.080 ;
    END
  END FrameData_O[15]
  PIN FrameData_O[16]
    DIRECTION OUTPUT ;
    USE SIGNAL ;
    ANTENNADIFFAREA 0.702900 ;
    PORT
      LAYER met3 ;
        RECT 210.080 176.840 210.680 177.440 ;
    END
  END FrameData_O[16]
  PIN FrameData_O[17]
    DIRECTION OUTPUT ;
    USE SIGNAL ;
    ANTENNADIFFAREA 0.702900 ;
    PORT
      LAYER met3 ;
        RECT 210.080 178.200 210.680 178.800 ;
    END
  END FrameData_O[17]
  PIN FrameData_O[18]
    DIRECTION OUTPUT ;
    USE SIGNAL ;
    ANTENNADIFFAREA 0.702900 ;
    PORT
      LAYER met3 ;
        RECT 210.080 179.560 210.680 180.160 ;
    END
  END FrameData_O[18]
  PIN FrameData_O[19]
    DIRECTION OUTPUT ;
    USE SIGNAL ;
    ANTENNADIFFAREA 0.702900 ;
    PORT
      LAYER met3 ;
        RECT 210.080 180.920 210.680 181.520 ;
    END
  END FrameData_O[19]
  PIN FrameData_O[1]
    DIRECTION OUTPUT ;
    USE SIGNAL ;
    ANTENNADIFFAREA 0.702900 ;
    PORT
      LAYER met3 ;
        RECT 210.080 156.440 210.680 157.040 ;
    END
  END FrameData_O[1]
  PIN FrameData_O[20]
    DIRECTION OUTPUT ;
    USE SIGNAL ;
    ANTENNADIFFAREA 0.702900 ;
    PORT
      LAYER met3 ;
        RECT 210.080 182.280 210.680 182.880 ;
    END
  END FrameData_O[20]
  PIN FrameData_O[21]
    DIRECTION OUTPUT ;
    USE SIGNAL ;
    ANTENNADIFFAREA 0.702900 ;
    PORT
      LAYER met3 ;
        RECT 210.080 183.640 210.680 184.240 ;
    END
  END FrameData_O[21]
  PIN FrameData_O[22]
    DIRECTION OUTPUT ;
    USE SIGNAL ;
    ANTENNADIFFAREA 0.702900 ;
    PORT
      LAYER met3 ;
        RECT 210.080 185.000 210.680 185.600 ;
    END
  END FrameData_O[22]
  PIN FrameData_O[23]
    DIRECTION OUTPUT ;
    USE SIGNAL ;
    ANTENNADIFFAREA 0.702900 ;
    PORT
      LAYER met3 ;
        RECT 210.080 186.360 210.680 186.960 ;
    END
  END FrameData_O[23]
  PIN FrameData_O[24]
    DIRECTION OUTPUT ;
    USE SIGNAL ;
    ANTENNADIFFAREA 0.702900 ;
    PORT
      LAYER met3 ;
        RECT 210.080 187.720 210.680 188.320 ;
    END
  END FrameData_O[24]
  PIN FrameData_O[25]
    DIRECTION OUTPUT ;
    USE SIGNAL ;
    ANTENNADIFFAREA 0.702900 ;
    PORT
      LAYER met3 ;
        RECT 210.080 189.080 210.680 189.680 ;
    END
  END FrameData_O[25]
  PIN FrameData_O[26]
    DIRECTION OUTPUT ;
    USE SIGNAL ;
    ANTENNADIFFAREA 0.702900 ;
    PORT
      LAYER met3 ;
        RECT 210.080 190.440 210.680 191.040 ;
    END
  END FrameData_O[26]
  PIN FrameData_O[27]
    DIRECTION OUTPUT ;
    USE SIGNAL ;
    ANTENNADIFFAREA 0.702900 ;
    PORT
      LAYER met3 ;
        RECT 210.080 191.800 210.680 192.400 ;
    END
  END FrameData_O[27]
  PIN FrameData_O[28]
    DIRECTION OUTPUT ;
    USE SIGNAL ;
    ANTENNADIFFAREA 0.702900 ;
    PORT
      LAYER met3 ;
        RECT 210.080 193.160 210.680 193.760 ;
    END
  END FrameData_O[28]
  PIN FrameData_O[29]
    DIRECTION OUTPUT ;
    USE SIGNAL ;
    ANTENNADIFFAREA 0.702900 ;
    PORT
      LAYER met3 ;
        RECT 210.080 194.520 210.680 195.120 ;
    END
  END FrameData_O[29]
  PIN FrameData_O[2]
    DIRECTION OUTPUT ;
    USE SIGNAL ;
    ANTENNADIFFAREA 0.702900 ;
    PORT
      LAYER met3 ;
        RECT 210.080 157.800 210.680 158.400 ;
    END
  END FrameData_O[2]
  PIN FrameData_O[30]
    DIRECTION OUTPUT ;
    USE SIGNAL ;
    ANTENNADIFFAREA 0.702900 ;
    PORT
      LAYER met3 ;
        RECT 210.080 195.880 210.680 196.480 ;
    END
  END FrameData_O[30]
  PIN FrameData_O[31]
    DIRECTION OUTPUT ;
    USE SIGNAL ;
    ANTENNADIFFAREA 0.702900 ;
    PORT
      LAYER met3 ;
        RECT 210.080 197.240 210.680 197.840 ;
    END
  END FrameData_O[31]
  PIN FrameData_O[3]
    DIRECTION OUTPUT ;
    USE SIGNAL ;
    ANTENNADIFFAREA 0.702900 ;
    PORT
      LAYER met3 ;
        RECT 210.080 159.160 210.680 159.760 ;
    END
  END FrameData_O[3]
  PIN FrameData_O[4]
    DIRECTION OUTPUT ;
    USE SIGNAL ;
    ANTENNADIFFAREA 0.702900 ;
    PORT
      LAYER met3 ;
        RECT 210.080 160.520 210.680 161.120 ;
    END
  END FrameData_O[4]
  PIN FrameData_O[5]
    DIRECTION OUTPUT ;
    USE SIGNAL ;
    ANTENNADIFFAREA 0.702900 ;
    PORT
      LAYER met3 ;
        RECT 210.080 161.880 210.680 162.480 ;
    END
  END FrameData_O[5]
  PIN FrameData_O[6]
    DIRECTION OUTPUT ;
    USE SIGNAL ;
    ANTENNADIFFAREA 0.702900 ;
    PORT
      LAYER met3 ;
        RECT 210.080 163.240 210.680 163.840 ;
    END
  END FrameData_O[6]
  PIN FrameData_O[7]
    DIRECTION OUTPUT ;
    USE SIGNAL ;
    ANTENNADIFFAREA 0.702900 ;
    PORT
      LAYER met3 ;
        RECT 210.080 164.600 210.680 165.200 ;
    END
  END FrameData_O[7]
  PIN FrameData_O[8]
    DIRECTION OUTPUT ;
    USE SIGNAL ;
    ANTENNADIFFAREA 0.702900 ;
    PORT
      LAYER met3 ;
        RECT 210.080 165.960 210.680 166.560 ;
    END
  END FrameData_O[8]
  PIN FrameData_O[9]
    DIRECTION OUTPUT ;
    USE SIGNAL ;
    ANTENNADIFFAREA 0.702900 ;
    PORT
      LAYER met3 ;
        RECT 210.080 167.320 210.680 167.920 ;
    END
  END FrameData_O[9]
  PIN FrameStrobe[0]
    DIRECTION INPUT ;
    USE SIGNAL ;
    ANTENNAGATEAREA 5.247000 ;
    PORT
      LAYER met2 ;
        RECT 167.070 0.000 167.350 0.280 ;
    END
  END FrameStrobe[0]
  PIN FrameStrobe[10]
    DIRECTION INPUT ;
    USE SIGNAL ;
    ANTENNAGATEAREA 5.247000 ;
    PORT
      LAYER met2 ;
        RECT 180.870 0.000 181.150 0.280 ;
    END
  END FrameStrobe[10]
  PIN FrameStrobe[11]
    DIRECTION INPUT ;
    USE SIGNAL ;
    ANTENNAGATEAREA 5.247000 ;
    PORT
      LAYER met2 ;
        RECT 182.250 0.000 182.530 0.280 ;
    END
  END FrameStrobe[11]
  PIN FrameStrobe[12]
    DIRECTION INPUT ;
    USE SIGNAL ;
    ANTENNAGATEAREA 5.247000 ;
    PORT
      LAYER met2 ;
        RECT 183.630 0.000 183.910 0.280 ;
    END
  END FrameStrobe[12]
  PIN FrameStrobe[13]
    DIRECTION INPUT ;
    USE SIGNAL ;
    ANTENNAGATEAREA 5.247000 ;
    PORT
      LAYER met2 ;
        RECT 185.010 0.000 185.290 0.280 ;
    END
  END FrameStrobe[13]
  PIN FrameStrobe[14]
    DIRECTION INPUT ;
    USE SIGNAL ;
    ANTENNAGATEAREA 5.247000 ;
    PORT
      LAYER met2 ;
        RECT 186.390 0.000 186.670 0.280 ;
    END
  END FrameStrobe[14]
  PIN FrameStrobe[15]
    DIRECTION INPUT ;
    USE SIGNAL ;
    ANTENNAGATEAREA 5.247000 ;
    PORT
      LAYER met2 ;
        RECT 187.770 0.000 188.050 0.280 ;
    END
  END FrameStrobe[15]
  PIN FrameStrobe[16]
    DIRECTION INPUT ;
    USE SIGNAL ;
    ANTENNAGATEAREA 5.681700 ;
    ANTENNADIFFAREA 0.434700 ;
    PORT
      LAYER met2 ;
        RECT 189.150 0.000 189.430 0.280 ;
    END
  END FrameStrobe[16]
  PIN FrameStrobe[17]
    DIRECTION INPUT ;
    USE SIGNAL ;
    ANTENNAGATEAREA 5.247000 ;
    PORT
      LAYER met2 ;
        RECT 190.530 0.000 190.810 0.280 ;
    END
  END FrameStrobe[17]
  PIN FrameStrobe[18]
    DIRECTION INPUT ;
    USE SIGNAL ;
    ANTENNAGATEAREA 5.247000 ;
    PORT
      LAYER met2 ;
        RECT 191.910 0.000 192.190 0.280 ;
    END
  END FrameStrobe[18]
  PIN FrameStrobe[19]
    DIRECTION INPUT ;
    USE SIGNAL ;
    ANTENNAGATEAREA 1.113000 ;
    PORT
      LAYER met2 ;
        RECT 193.290 0.000 193.570 0.280 ;
    END
  END FrameStrobe[19]
  PIN FrameStrobe[1]
    DIRECTION INPUT ;
    USE SIGNAL ;
    ANTENNAGATEAREA 5.247000 ;
    PORT
      LAYER met2 ;
        RECT 168.450 0.000 168.730 0.280 ;
    END
  END FrameStrobe[1]
  PIN FrameStrobe[2]
    DIRECTION INPUT ;
    USE SIGNAL ;
    ANTENNAGATEAREA 5.247000 ;
    PORT
      LAYER met2 ;
        RECT 169.830 0.000 170.110 0.280 ;
    END
  END FrameStrobe[2]
  PIN FrameStrobe[3]
    DIRECTION INPUT ;
    USE SIGNAL ;
    ANTENNAGATEAREA 5.247000 ;
    PORT
      LAYER met2 ;
        RECT 171.210 0.000 171.490 0.280 ;
    END
  END FrameStrobe[3]
  PIN FrameStrobe[4]
    DIRECTION INPUT ;
    USE SIGNAL ;
    ANTENNAGATEAREA 5.247000 ;
    PORT
      LAYER met2 ;
        RECT 172.590 0.000 172.870 0.280 ;
    END
  END FrameStrobe[4]
  PIN FrameStrobe[5]
    DIRECTION INPUT ;
    USE SIGNAL ;
    ANTENNAGATEAREA 5.247000 ;
    PORT
      LAYER met2 ;
        RECT 173.970 0.000 174.250 0.280 ;
    END
  END FrameStrobe[5]
  PIN FrameStrobe[6]
    DIRECTION INPUT ;
    USE SIGNAL ;
    ANTENNAGATEAREA 5.247000 ;
    PORT
      LAYER met2 ;
        RECT 175.350 0.000 175.630 0.280 ;
    END
  END FrameStrobe[6]
  PIN FrameStrobe[7]
    DIRECTION INPUT ;
    USE SIGNAL ;
    ANTENNAGATEAREA 5.247000 ;
    PORT
      LAYER met2 ;
        RECT 176.730 0.000 177.010 0.280 ;
    END
  END FrameStrobe[7]
  PIN FrameStrobe[8]
    DIRECTION INPUT ;
    USE SIGNAL ;
    ANTENNAGATEAREA 5.247000 ;
    PORT
      LAYER met2 ;
        RECT 178.110 0.000 178.390 0.280 ;
    END
  END FrameStrobe[8]
  PIN FrameStrobe[9]
    DIRECTION INPUT ;
    USE SIGNAL ;
    ANTENNAGATEAREA 5.681700 ;
    ANTENNADIFFAREA 0.434700 ;
    PORT
      LAYER met2 ;
        RECT 179.490 0.000 179.770 0.280 ;
    END
  END FrameStrobe[9]
  PIN FrameStrobe_O[0]
    DIRECTION OUTPUT ;
    USE SIGNAL ;
    ANTENNADIFFAREA 0.702900 ;
    PORT
      LAYER met2 ;
        RECT 167.070 222.760 167.350 223.040 ;
    END
  END FrameStrobe_O[0]
  PIN FrameStrobe_O[10]
    DIRECTION OUTPUT ;
    USE SIGNAL ;
    ANTENNADIFFAREA 0.702900 ;
    PORT
      LAYER met2 ;
        RECT 180.870 222.760 181.150 223.040 ;
    END
  END FrameStrobe_O[10]
  PIN FrameStrobe_O[11]
    DIRECTION OUTPUT ;
    USE SIGNAL ;
    ANTENNADIFFAREA 0.702900 ;
    PORT
      LAYER met2 ;
        RECT 182.250 222.760 182.530 223.040 ;
    END
  END FrameStrobe_O[11]
  PIN FrameStrobe_O[12]
    DIRECTION OUTPUT ;
    USE SIGNAL ;
    ANTENNADIFFAREA 0.702900 ;
    PORT
      LAYER met2 ;
        RECT 183.630 222.760 183.910 223.040 ;
    END
  END FrameStrobe_O[12]
  PIN FrameStrobe_O[13]
    DIRECTION OUTPUT ;
    USE SIGNAL ;
    ANTENNADIFFAREA 0.702900 ;
    PORT
      LAYER met2 ;
        RECT 185.010 222.760 185.290 223.040 ;
    END
  END FrameStrobe_O[13]
  PIN FrameStrobe_O[14]
    DIRECTION OUTPUT ;
    USE SIGNAL ;
    ANTENNADIFFAREA 0.702900 ;
    PORT
      LAYER met2 ;
        RECT 186.390 222.760 186.670 223.040 ;
    END
  END FrameStrobe_O[14]
  PIN FrameStrobe_O[15]
    DIRECTION OUTPUT ;
    USE SIGNAL ;
    ANTENNADIFFAREA 0.702900 ;
    PORT
      LAYER met2 ;
        RECT 187.770 222.760 188.050 223.040 ;
    END
  END FrameStrobe_O[15]
  PIN FrameStrobe_O[16]
    DIRECTION OUTPUT ;
    USE SIGNAL ;
    ANTENNADIFFAREA 0.702900 ;
    PORT
      LAYER met2 ;
        RECT 189.150 222.760 189.430 223.040 ;
    END
  END FrameStrobe_O[16]
  PIN FrameStrobe_O[17]
    DIRECTION OUTPUT ;
    USE SIGNAL ;
    ANTENNADIFFAREA 0.702900 ;
    PORT
      LAYER met2 ;
        RECT 190.530 222.760 190.810 223.040 ;
    END
  END FrameStrobe_O[17]
  PIN FrameStrobe_O[18]
    DIRECTION OUTPUT ;
    USE SIGNAL ;
    ANTENNADIFFAREA 0.702900 ;
    PORT
      LAYER met2 ;
        RECT 191.910 222.760 192.190 223.040 ;
    END
  END FrameStrobe_O[18]
  PIN FrameStrobe_O[19]
    DIRECTION OUTPUT ;
    USE SIGNAL ;
    ANTENNADIFFAREA 0.702900 ;
    PORT
      LAYER met2 ;
        RECT 193.290 222.760 193.570 223.040 ;
    END
  END FrameStrobe_O[19]
  PIN FrameStrobe_O[1]
    DIRECTION OUTPUT ;
    USE SIGNAL ;
    ANTENNADIFFAREA 0.702900 ;
    PORT
      LAYER met2 ;
        RECT 168.450 222.760 168.730 223.040 ;
    END
  END FrameStrobe_O[1]
  PIN FrameStrobe_O[2]
    DIRECTION OUTPUT ;
    USE SIGNAL ;
    ANTENNADIFFAREA 0.702900 ;
    PORT
      LAYER met2 ;
        RECT 169.830 222.760 170.110 223.040 ;
    END
  END FrameStrobe_O[2]
  PIN FrameStrobe_O[3]
    DIRECTION OUTPUT ;
    USE SIGNAL ;
    ANTENNADIFFAREA 0.702900 ;
    PORT
      LAYER met2 ;
        RECT 171.210 222.760 171.490 223.040 ;
    END
  END FrameStrobe_O[3]
  PIN FrameStrobe_O[4]
    DIRECTION OUTPUT ;
    USE SIGNAL ;
    ANTENNADIFFAREA 0.702900 ;
    PORT
      LAYER met2 ;
        RECT 172.590 222.760 172.870 223.040 ;
    END
  END FrameStrobe_O[4]
  PIN FrameStrobe_O[5]
    DIRECTION OUTPUT ;
    USE SIGNAL ;
    ANTENNADIFFAREA 0.702900 ;
    PORT
      LAYER met2 ;
        RECT 173.970 222.760 174.250 223.040 ;
    END
  END FrameStrobe_O[5]
  PIN FrameStrobe_O[6]
    DIRECTION OUTPUT ;
    USE SIGNAL ;
    ANTENNADIFFAREA 0.702900 ;
    PORT
      LAYER met2 ;
        RECT 175.350 222.760 175.630 223.040 ;
    END
  END FrameStrobe_O[6]
  PIN FrameStrobe_O[7]
    DIRECTION OUTPUT ;
    USE SIGNAL ;
    ANTENNADIFFAREA 0.702900 ;
    PORT
      LAYER met2 ;
        RECT 176.730 222.760 177.010 223.040 ;
    END
  END FrameStrobe_O[7]
  PIN FrameStrobe_O[8]
    DIRECTION OUTPUT ;
    USE SIGNAL ;
    ANTENNADIFFAREA 0.702900 ;
    PORT
      LAYER met2 ;
        RECT 178.110 222.760 178.390 223.040 ;
    END
  END FrameStrobe_O[8]
  PIN FrameStrobe_O[9]
    DIRECTION OUTPUT ;
    USE SIGNAL ;
    ANTENNADIFFAREA 0.702900 ;
    PORT
      LAYER met2 ;
        RECT 179.490 222.760 179.770 223.040 ;
    END
  END FrameStrobe_O[9]
  PIN N1BEG[0]
    DIRECTION OUTPUT ;
    USE SIGNAL ;
    ANTENNADIFFAREA 0.702900 ;
    PORT
      LAYER met2 ;
        RECT 22.170 222.760 22.450 223.040 ;
    END
  END N1BEG[0]
  PIN N1BEG[1]
    DIRECTION OUTPUT ;
    USE SIGNAL ;
    ANTENNADIFFAREA 0.702900 ;
    PORT
      LAYER met2 ;
        RECT 23.550 222.760 23.830 223.040 ;
    END
  END N1BEG[1]
  PIN N1BEG[2]
    DIRECTION OUTPUT ;
    USE SIGNAL ;
    ANTENNADIFFAREA 0.702900 ;
    PORT
      LAYER met2 ;
        RECT 24.930 222.760 25.210 223.040 ;
    END
  END N1BEG[2]
  PIN N1BEG[3]
    DIRECTION OUTPUT ;
    USE SIGNAL ;
    ANTENNADIFFAREA 0.702900 ;
    PORT
      LAYER met2 ;
        RECT 26.310 222.760 26.590 223.040 ;
    END
  END N1BEG[3]
  PIN N1END[0]
    DIRECTION INPUT ;
    USE SIGNAL ;
    ANTENNAGATEAREA 2.898000 ;
    PORT
      LAYER met2 ;
        RECT 22.170 0.000 22.450 0.280 ;
    END
  END N1END[0]
  PIN N1END[1]
    DIRECTION INPUT ;
    USE SIGNAL ;
    ANTENNAGATEAREA 2.226000 ;
    PORT
      LAYER met2 ;
        RECT 23.550 0.000 23.830 0.280 ;
    END
  END N1END[1]
  PIN N1END[2]
    DIRECTION INPUT ;
    USE SIGNAL ;
    ANTENNAGATEAREA 2.544000 ;
    PORT
      LAYER met2 ;
        RECT 24.930 0.000 25.210 0.280 ;
    END
  END N1END[2]
  PIN N1END[3]
    DIRECTION INPUT ;
    USE SIGNAL ;
    ANTENNAGATEAREA 2.544000 ;
    PORT
      LAYER met2 ;
        RECT 26.310 0.000 26.590 0.280 ;
    END
  END N1END[3]
  PIN N2BEG[0]
    DIRECTION OUTPUT ;
    USE SIGNAL ;
    ANTENNADIFFAREA 0.702900 ;
    PORT
      LAYER met2 ;
        RECT 27.690 222.760 27.970 223.040 ;
    END
  END N2BEG[0]
  PIN N2BEG[1]
    DIRECTION OUTPUT ;
    USE SIGNAL ;
    ANTENNADIFFAREA 0.702900 ;
    PORT
      LAYER met2 ;
        RECT 29.070 222.760 29.350 223.040 ;
    END
  END N2BEG[1]
  PIN N2BEG[2]
    DIRECTION OUTPUT ;
    USE SIGNAL ;
    ANTENNADIFFAREA 0.702900 ;
    PORT
      LAYER met2 ;
        RECT 30.450 222.760 30.730 223.040 ;
    END
  END N2BEG[2]
  PIN N2BEG[3]
    DIRECTION OUTPUT ;
    USE SIGNAL ;
    ANTENNADIFFAREA 0.702900 ;
    PORT
      LAYER met2 ;
        RECT 31.830 222.760 32.110 223.040 ;
    END
  END N2BEG[3]
  PIN N2BEG[4]
    DIRECTION OUTPUT ;
    USE SIGNAL ;
    ANTENNADIFFAREA 0.702900 ;
    PORT
      LAYER met2 ;
        RECT 33.210 222.760 33.490 223.040 ;
    END
  END N2BEG[4]
  PIN N2BEG[5]
    DIRECTION OUTPUT ;
    USE SIGNAL ;
    ANTENNADIFFAREA 0.702900 ;
    PORT
      LAYER met2 ;
        RECT 34.590 222.760 34.870 223.040 ;
    END
  END N2BEG[5]
  PIN N2BEG[6]
    DIRECTION OUTPUT ;
    USE SIGNAL ;
    ANTENNADIFFAREA 0.702900 ;
    PORT
      LAYER met2 ;
        RECT 35.970 222.760 36.250 223.040 ;
    END
  END N2BEG[6]
  PIN N2BEG[7]
    DIRECTION OUTPUT ;
    USE SIGNAL ;
    ANTENNADIFFAREA 0.702900 ;
    PORT
      LAYER met2 ;
        RECT 37.350 222.760 37.630 223.040 ;
    END
  END N2BEG[7]
  PIN N2BEGb[0]
    DIRECTION OUTPUT ;
    USE SIGNAL ;
    ANTENNADIFFAREA 0.702900 ;
    PORT
      LAYER met2 ;
        RECT 38.730 222.760 39.010 223.040 ;
    END
  END N2BEGb[0]
  PIN N2BEGb[1]
    DIRECTION OUTPUT ;
    USE SIGNAL ;
    ANTENNADIFFAREA 0.702900 ;
    PORT
      LAYER met2 ;
        RECT 40.110 222.760 40.390 223.040 ;
    END
  END N2BEGb[1]
  PIN N2BEGb[2]
    DIRECTION OUTPUT ;
    USE SIGNAL ;
    ANTENNADIFFAREA 0.702900 ;
    PORT
      LAYER met2 ;
        RECT 41.490 222.760 41.770 223.040 ;
    END
  END N2BEGb[2]
  PIN N2BEGb[3]
    DIRECTION OUTPUT ;
    USE SIGNAL ;
    ANTENNADIFFAREA 0.702900 ;
    PORT
      LAYER met2 ;
        RECT 42.870 222.760 43.150 223.040 ;
    END
  END N2BEGb[3]
  PIN N2BEGb[4]
    DIRECTION OUTPUT ;
    USE SIGNAL ;
    ANTENNADIFFAREA 0.702900 ;
    PORT
      LAYER met2 ;
        RECT 44.250 222.760 44.530 223.040 ;
    END
  END N2BEGb[4]
  PIN N2BEGb[5]
    DIRECTION OUTPUT ;
    USE SIGNAL ;
    ANTENNADIFFAREA 0.702900 ;
    PORT
      LAYER met2 ;
        RECT 45.630 222.760 45.910 223.040 ;
    END
  END N2BEGb[5]
  PIN N2BEGb[6]
    DIRECTION OUTPUT ;
    USE SIGNAL ;
    ANTENNADIFFAREA 0.702900 ;
    PORT
      LAYER met2 ;
        RECT 47.010 222.760 47.290 223.040 ;
    END
  END N2BEGb[6]
  PIN N2BEGb[7]
    DIRECTION OUTPUT ;
    USE SIGNAL ;
    ANTENNADIFFAREA 0.702900 ;
    PORT
      LAYER met2 ;
        RECT 48.390 222.760 48.670 223.040 ;
    END
  END N2BEGb[7]
  PIN N2END[0]
    DIRECTION INPUT ;
    USE SIGNAL ;
    ANTENNAGATEAREA 0.954000 ;
    PORT
      LAYER met2 ;
        RECT 38.730 0.000 39.010 0.280 ;
    END
  END N2END[0]
  PIN N2END[1]
    DIRECTION INPUT ;
    USE SIGNAL ;
    ANTENNAGATEAREA 0.795000 ;
    PORT
      LAYER met2 ;
        RECT 40.110 0.000 40.390 0.280 ;
    END
  END N2END[1]
  PIN N2END[2]
    DIRECTION INPUT ;
    USE SIGNAL ;
    ANTENNAGATEAREA 0.795000 ;
    PORT
      LAYER met2 ;
        RECT 41.490 0.000 41.770 0.280 ;
    END
  END N2END[2]
  PIN N2END[3]
    DIRECTION INPUT ;
    USE SIGNAL ;
    ANTENNAGATEAREA 1.388700 ;
    ANTENNADIFFAREA 0.434700 ;
    PORT
      LAYER met2 ;
        RECT 42.870 0.000 43.150 0.280 ;
    END
  END N2END[3]
  PIN N2END[4]
    DIRECTION INPUT ;
    USE SIGNAL ;
    ANTENNAGATEAREA 0.954000 ;
    PORT
      LAYER met2 ;
        RECT 44.250 0.000 44.530 0.280 ;
    END
  END N2END[4]
  PIN N2END[5]
    DIRECTION INPUT ;
    USE SIGNAL ;
    ANTENNAGATEAREA 0.795000 ;
    PORT
      LAYER met2 ;
        RECT 45.630 0.000 45.910 0.280 ;
    END
  END N2END[5]
  PIN N2END[6]
    DIRECTION INPUT ;
    USE SIGNAL ;
    ANTENNAGATEAREA 0.795000 ;
    PORT
      LAYER met2 ;
        RECT 47.010 0.000 47.290 0.280 ;
    END
  END N2END[6]
  PIN N2END[7]
    DIRECTION INPUT ;
    USE SIGNAL ;
    ANTENNAGATEAREA 0.954000 ;
    PORT
      LAYER met2 ;
        RECT 48.390 0.000 48.670 0.280 ;
    END
  END N2END[7]
  PIN N2MID[0]
    DIRECTION INPUT ;
    USE SIGNAL ;
    ANTENNAGATEAREA 2.374800 ;
    ANTENNADIFFAREA 1.738800 ;
    PORT
      LAYER met2 ;
        RECT 27.690 0.000 27.970 0.280 ;
    END
  END N2MID[0]
  PIN N2MID[1]
    DIRECTION INPUT ;
    USE SIGNAL ;
    ANTENNAGATEAREA 0.795000 ;
    PORT
      LAYER met2 ;
        RECT 29.070 0.000 29.350 0.280 ;
    END
  END N2MID[1]
  PIN N2MID[2]
    DIRECTION INPUT ;
    USE SIGNAL ;
    ANTENNAGATEAREA 1.940100 ;
    ANTENNADIFFAREA 1.304100 ;
    PORT
      LAYER met2 ;
        RECT 30.450 0.000 30.730 0.280 ;
    END
  END N2MID[2]
  PIN N2MID[3]
    DIRECTION INPUT ;
    USE SIGNAL ;
    ANTENNAGATEAREA 0.795000 ;
    PORT
      LAYER met2 ;
        RECT 31.830 0.000 32.110 0.280 ;
    END
  END N2MID[3]
  PIN N2MID[4]
    DIRECTION INPUT ;
    USE SIGNAL ;
    ANTENNAGATEAREA 1.532700 ;
    ANTENNADIFFAREA 0.434700 ;
    PORT
      LAYER met2 ;
        RECT 33.210 0.000 33.490 0.280 ;
    END
  END N2MID[4]
  PIN N2MID[5]
    DIRECTION INPUT ;
    USE SIGNAL ;
    ANTENNAGATEAREA 0.795000 ;
    PORT
      LAYER met2 ;
        RECT 34.590 0.000 34.870 0.280 ;
    END
  END N2MID[5]
  PIN N2MID[6]
    DIRECTION INPUT ;
    USE SIGNAL ;
    ANTENNAGATEAREA 2.374800 ;
    ANTENNADIFFAREA 1.738800 ;
    PORT
      LAYER met2 ;
        RECT 35.970 0.000 36.250 0.280 ;
    END
  END N2MID[6]
  PIN N2MID[7]
    DIRECTION INPUT ;
    USE SIGNAL ;
    ANTENNAGATEAREA 0.795000 ;
    PORT
      LAYER met2 ;
        RECT 37.350 0.000 37.630 0.280 ;
    END
  END N2MID[7]
  PIN N4BEG[0]
    DIRECTION OUTPUT ;
    USE SIGNAL ;
    ANTENNADIFFAREA 0.702900 ;
    PORT
      LAYER met2 ;
        RECT 49.770 222.760 50.050 223.040 ;
    END
  END N4BEG[0]
  PIN N4BEG[10]
    DIRECTION OUTPUT ;
    USE SIGNAL ;
    ANTENNADIFFAREA 0.702900 ;
    PORT
      LAYER met2 ;
        RECT 63.570 222.760 63.850 223.040 ;
    END
  END N4BEG[10]
  PIN N4BEG[11]
    DIRECTION OUTPUT ;
    USE SIGNAL ;
    ANTENNADIFFAREA 0.702900 ;
    PORT
      LAYER met2 ;
        RECT 64.950 222.760 65.230 223.040 ;
    END
  END N4BEG[11]
  PIN N4BEG[12]
    DIRECTION OUTPUT ;
    USE SIGNAL ;
    ANTENNADIFFAREA 0.702900 ;
    PORT
      LAYER met2 ;
        RECT 66.330 222.760 66.610 223.040 ;
    END
  END N4BEG[12]
  PIN N4BEG[13]
    DIRECTION OUTPUT ;
    USE SIGNAL ;
    ANTENNADIFFAREA 0.702900 ;
    PORT
      LAYER met2 ;
        RECT 67.710 222.760 67.990 223.040 ;
    END
  END N4BEG[13]
  PIN N4BEG[14]
    DIRECTION OUTPUT ;
    USE SIGNAL ;
    ANTENNADIFFAREA 0.702900 ;
    PORT
      LAYER met2 ;
        RECT 69.090 222.760 69.370 223.040 ;
    END
  END N4BEG[14]
  PIN N4BEG[15]
    DIRECTION OUTPUT ;
    USE SIGNAL ;
    ANTENNADIFFAREA 0.702900 ;
    PORT
      LAYER met2 ;
        RECT 70.470 222.760 70.750 223.040 ;
    END
  END N4BEG[15]
  PIN N4BEG[1]
    DIRECTION OUTPUT ;
    USE SIGNAL ;
    ANTENNADIFFAREA 0.702900 ;
    PORT
      LAYER met2 ;
        RECT 51.150 222.760 51.430 223.040 ;
    END
  END N4BEG[1]
  PIN N4BEG[2]
    DIRECTION OUTPUT ;
    USE SIGNAL ;
    ANTENNADIFFAREA 0.702900 ;
    PORT
      LAYER met2 ;
        RECT 52.530 222.760 52.810 223.040 ;
    END
  END N4BEG[2]
  PIN N4BEG[3]
    DIRECTION OUTPUT ;
    USE SIGNAL ;
    ANTENNADIFFAREA 0.702900 ;
    PORT
      LAYER met2 ;
        RECT 53.910 222.760 54.190 223.040 ;
    END
  END N4BEG[3]
  PIN N4BEG[4]
    DIRECTION OUTPUT ;
    USE SIGNAL ;
    ANTENNADIFFAREA 0.702900 ;
    PORT
      LAYER met2 ;
        RECT 55.290 222.760 55.570 223.040 ;
    END
  END N4BEG[4]
  PIN N4BEG[5]
    DIRECTION OUTPUT ;
    USE SIGNAL ;
    ANTENNADIFFAREA 0.702900 ;
    PORT
      LAYER met2 ;
        RECT 56.670 222.760 56.950 223.040 ;
    END
  END N4BEG[5]
  PIN N4BEG[6]
    DIRECTION OUTPUT ;
    USE SIGNAL ;
    ANTENNADIFFAREA 0.702900 ;
    PORT
      LAYER met2 ;
        RECT 58.050 222.760 58.330 223.040 ;
    END
  END N4BEG[6]
  PIN N4BEG[7]
    DIRECTION OUTPUT ;
    USE SIGNAL ;
    ANTENNADIFFAREA 0.702900 ;
    PORT
      LAYER met2 ;
        RECT 59.430 222.760 59.710 223.040 ;
    END
  END N4BEG[7]
  PIN N4BEG[8]
    DIRECTION OUTPUT ;
    USE SIGNAL ;
    ANTENNADIFFAREA 0.702900 ;
    PORT
      LAYER met2 ;
        RECT 60.810 222.760 61.090 223.040 ;
    END
  END N4BEG[8]
  PIN N4BEG[9]
    DIRECTION OUTPUT ;
    USE SIGNAL ;
    ANTENNADIFFAREA 0.702900 ;
    PORT
      LAYER met2 ;
        RECT 62.190 222.760 62.470 223.040 ;
    END
  END N4BEG[9]
  PIN N4END[0]
    DIRECTION INPUT ;
    USE SIGNAL ;
    ANTENNAGATEAREA 0.795000 ;
    PORT
      LAYER met2 ;
        RECT 49.770 0.000 50.050 0.280 ;
    END
  END N4END[0]
  PIN N4END[10]
    DIRECTION INPUT ;
    USE SIGNAL ;
    ANTENNAGATEAREA 0.159000 ;
    PORT
      LAYER met2 ;
        RECT 63.570 0.000 63.850 0.280 ;
    END
  END N4END[10]
  PIN N4END[11]
    DIRECTION INPUT ;
    USE SIGNAL ;
    ANTENNAGATEAREA 0.159000 ;
    PORT
      LAYER met2 ;
        RECT 64.950 0.000 65.230 0.280 ;
    END
  END N4END[11]
  PIN N4END[12]
    DIRECTION INPUT ;
    USE SIGNAL ;
    ANTENNAGATEAREA 0.159000 ;
    PORT
      LAYER met2 ;
        RECT 66.330 0.000 66.610 0.280 ;
    END
  END N4END[12]
  PIN N4END[13]
    DIRECTION INPUT ;
    USE SIGNAL ;
    ANTENNAGATEAREA 0.159000 ;
    PORT
      LAYER met2 ;
        RECT 67.710 0.000 67.990 0.280 ;
    END
  END N4END[13]
  PIN N4END[14]
    DIRECTION INPUT ;
    USE SIGNAL ;
    ANTENNAGATEAREA 0.159000 ;
    PORT
      LAYER met2 ;
        RECT 69.090 0.000 69.370 0.280 ;
    END
  END N4END[14]
  PIN N4END[15]
    DIRECTION INPUT ;
    USE SIGNAL ;
    ANTENNAGATEAREA 0.159000 ;
    PORT
      LAYER met2 ;
        RECT 70.470 0.000 70.750 0.280 ;
    END
  END N4END[15]
  PIN N4END[1]
    DIRECTION INPUT ;
    USE SIGNAL ;
    ANTENNAGATEAREA 0.795000 ;
    PORT
      LAYER met2 ;
        RECT 51.150 0.000 51.430 0.280 ;
    END
  END N4END[1]
  PIN N4END[2]
    DIRECTION INPUT ;
    USE SIGNAL ;
    ANTENNAGATEAREA 0.795000 ;
    PORT
      LAYER met2 ;
        RECT 52.530 0.000 52.810 0.280 ;
    END
  END N4END[2]
  PIN N4END[3]
    DIRECTION INPUT ;
    USE SIGNAL ;
    ANTENNAGATEAREA 1.229700 ;
    ANTENNADIFFAREA 0.434700 ;
    PORT
      LAYER met2 ;
        RECT 53.910 0.000 54.190 0.280 ;
    END
  END N4END[3]
  PIN N4END[4]
    DIRECTION INPUT ;
    USE SIGNAL ;
    ANTENNAGATEAREA 0.159000 ;
    PORT
      LAYER met2 ;
        RECT 55.290 0.000 55.570 0.280 ;
    END
  END N4END[4]
  PIN N4END[5]
    DIRECTION INPUT ;
    USE SIGNAL ;
    ANTENNAGATEAREA 0.159000 ;
    PORT
      LAYER met2 ;
        RECT 56.670 0.000 56.950 0.280 ;
    END
  END N4END[5]
  PIN N4END[6]
    DIRECTION INPUT ;
    USE SIGNAL ;
    ANTENNAGATEAREA 0.159000 ;
    PORT
      LAYER met2 ;
        RECT 58.050 0.000 58.330 0.280 ;
    END
  END N4END[6]
  PIN N4END[7]
    DIRECTION INPUT ;
    USE SIGNAL ;
    ANTENNAGATEAREA 0.159000 ;
    PORT
      LAYER met2 ;
        RECT 59.430 0.000 59.710 0.280 ;
    END
  END N4END[7]
  PIN N4END[8]
    DIRECTION INPUT ;
    USE SIGNAL ;
    ANTENNAGATEAREA 0.159000 ;
    PORT
      LAYER met2 ;
        RECT 60.810 0.000 61.090 0.280 ;
    END
  END N4END[8]
  PIN N4END[9]
    DIRECTION INPUT ;
    USE SIGNAL ;
    ANTENNAGATEAREA 0.159000 ;
    PORT
      LAYER met2 ;
        RECT 62.190 0.000 62.470 0.280 ;
    END
  END N4END[9]
  PIN NN4BEG[0]
    DIRECTION OUTPUT ;
    USE SIGNAL ;
    ANTENNADIFFAREA 0.702900 ;
    PORT
      LAYER met2 ;
        RECT 71.850 222.760 72.130 223.040 ;
    END
  END NN4BEG[0]
  PIN NN4BEG[10]
    DIRECTION OUTPUT ;
    USE SIGNAL ;
    ANTENNADIFFAREA 0.702900 ;
    PORT
      LAYER met2 ;
        RECT 85.650 222.760 85.930 223.040 ;
    END
  END NN4BEG[10]
  PIN NN4BEG[11]
    DIRECTION OUTPUT ;
    USE SIGNAL ;
    ANTENNADIFFAREA 0.702900 ;
    PORT
      LAYER met2 ;
        RECT 87.030 222.760 87.310 223.040 ;
    END
  END NN4BEG[11]
  PIN NN4BEG[12]
    DIRECTION OUTPUT ;
    USE SIGNAL ;
    ANTENNADIFFAREA 0.702900 ;
    PORT
      LAYER met2 ;
        RECT 88.410 222.760 88.690 223.040 ;
    END
  END NN4BEG[12]
  PIN NN4BEG[13]
    DIRECTION OUTPUT ;
    USE SIGNAL ;
    ANTENNADIFFAREA 0.702900 ;
    PORT
      LAYER met2 ;
        RECT 89.790 222.760 90.070 223.040 ;
    END
  END NN4BEG[13]
  PIN NN4BEG[14]
    DIRECTION OUTPUT ;
    USE SIGNAL ;
    ANTENNADIFFAREA 0.702900 ;
    PORT
      LAYER met2 ;
        RECT 91.170 222.760 91.450 223.040 ;
    END
  END NN4BEG[14]
  PIN NN4BEG[15]
    DIRECTION OUTPUT ;
    USE SIGNAL ;
    ANTENNADIFFAREA 0.702900 ;
    PORT
      LAYER met2 ;
        RECT 92.550 222.760 92.830 223.040 ;
    END
  END NN4BEG[15]
  PIN NN4BEG[1]
    DIRECTION OUTPUT ;
    USE SIGNAL ;
    ANTENNADIFFAREA 0.702900 ;
    PORT
      LAYER met2 ;
        RECT 73.230 222.760 73.510 223.040 ;
    END
  END NN4BEG[1]
  PIN NN4BEG[2]
    DIRECTION OUTPUT ;
    USE SIGNAL ;
    ANTENNADIFFAREA 0.702900 ;
    PORT
      LAYER met2 ;
        RECT 74.610 222.760 74.890 223.040 ;
    END
  END NN4BEG[2]
  PIN NN4BEG[3]
    DIRECTION OUTPUT ;
    USE SIGNAL ;
    ANTENNADIFFAREA 0.702900 ;
    PORT
      LAYER met2 ;
        RECT 75.990 222.760 76.270 223.040 ;
    END
  END NN4BEG[3]
  PIN NN4BEG[4]
    DIRECTION OUTPUT ;
    USE SIGNAL ;
    ANTENNADIFFAREA 0.702900 ;
    PORT
      LAYER met2 ;
        RECT 77.370 222.760 77.650 223.040 ;
    END
  END NN4BEG[4]
  PIN NN4BEG[5]
    DIRECTION OUTPUT ;
    USE SIGNAL ;
    ANTENNADIFFAREA 0.702900 ;
    PORT
      LAYER met2 ;
        RECT 78.750 222.760 79.030 223.040 ;
    END
  END NN4BEG[5]
  PIN NN4BEG[6]
    DIRECTION OUTPUT ;
    USE SIGNAL ;
    ANTENNADIFFAREA 0.702900 ;
    PORT
      LAYER met2 ;
        RECT 80.130 222.760 80.410 223.040 ;
    END
  END NN4BEG[6]
  PIN NN4BEG[7]
    DIRECTION OUTPUT ;
    USE SIGNAL ;
    ANTENNADIFFAREA 0.702900 ;
    PORT
      LAYER met2 ;
        RECT 81.510 222.760 81.790 223.040 ;
    END
  END NN4BEG[7]
  PIN NN4BEG[8]
    DIRECTION OUTPUT ;
    USE SIGNAL ;
    ANTENNADIFFAREA 0.702900 ;
    PORT
      LAYER met2 ;
        RECT 82.890 222.760 83.170 223.040 ;
    END
  END NN4BEG[8]
  PIN NN4BEG[9]
    DIRECTION OUTPUT ;
    USE SIGNAL ;
    ANTENNADIFFAREA 0.702900 ;
    PORT
      LAYER met2 ;
        RECT 84.270 222.760 84.550 223.040 ;
    END
  END NN4BEG[9]
  PIN NN4END[0]
    DIRECTION INPUT ;
    USE SIGNAL ;
    ANTENNAGATEAREA 0.477000 ;
    PORT
      LAYER met2 ;
        RECT 71.850 0.000 72.130 0.280 ;
    END
  END NN4END[0]
  PIN NN4END[10]
    DIRECTION INPUT ;
    USE SIGNAL ;
    ANTENNAGATEAREA 0.159000 ;
    PORT
      LAYER met2 ;
        RECT 85.650 0.000 85.930 0.280 ;
    END
  END NN4END[10]
  PIN NN4END[11]
    DIRECTION INPUT ;
    USE SIGNAL ;
    ANTENNAGATEAREA 0.159000 ;
    PORT
      LAYER met2 ;
        RECT 87.030 0.000 87.310 0.280 ;
    END
  END NN4END[11]
  PIN NN4END[12]
    DIRECTION INPUT ;
    USE SIGNAL ;
    ANTENNAGATEAREA 0.159000 ;
    PORT
      LAYER met2 ;
        RECT 88.410 0.000 88.690 0.280 ;
    END
  END NN4END[12]
  PIN NN4END[13]
    DIRECTION INPUT ;
    USE SIGNAL ;
    ANTENNAGATEAREA 0.159000 ;
    PORT
      LAYER met2 ;
        RECT 89.790 0.000 90.070 0.280 ;
    END
  END NN4END[13]
  PIN NN4END[14]
    DIRECTION INPUT ;
    USE SIGNAL ;
    ANTENNAGATEAREA 0.159000 ;
    PORT
      LAYER met2 ;
        RECT 91.170 0.000 91.450 0.280 ;
    END
  END NN4END[14]
  PIN NN4END[15]
    DIRECTION INPUT ;
    USE SIGNAL ;
    ANTENNAGATEAREA 0.159000 ;
    PORT
      LAYER met2 ;
        RECT 92.550 0.000 92.830 0.280 ;
    END
  END NN4END[15]
  PIN NN4END[1]
    DIRECTION INPUT ;
    USE SIGNAL ;
    ANTENNAGATEAREA 0.911700 ;
    ANTENNADIFFAREA 0.434700 ;
    PORT
      LAYER met2 ;
        RECT 73.230 0.000 73.510 0.280 ;
    END
  END NN4END[1]
  PIN NN4END[2]
    DIRECTION INPUT ;
    USE SIGNAL ;
    ANTENNAGATEAREA 0.911700 ;
    ANTENNADIFFAREA 0.434700 ;
    PORT
      LAYER met2 ;
        RECT 74.610 0.000 74.890 0.280 ;
    END
  END NN4END[2]
  PIN NN4END[3]
    DIRECTION INPUT ;
    USE SIGNAL ;
    ANTENNAGATEAREA 0.911700 ;
    ANTENNADIFFAREA 0.434700 ;
    PORT
      LAYER met2 ;
        RECT 75.990 0.000 76.270 0.280 ;
    END
  END NN4END[3]
  PIN NN4END[4]
    DIRECTION INPUT ;
    USE SIGNAL ;
    ANTENNAGATEAREA 0.159000 ;
    PORT
      LAYER met2 ;
        RECT 77.370 0.000 77.650 0.280 ;
    END
  END NN4END[4]
  PIN NN4END[5]
    DIRECTION INPUT ;
    USE SIGNAL ;
    ANTENNAGATEAREA 0.159000 ;
    PORT
      LAYER met2 ;
        RECT 78.750 0.000 79.030 0.280 ;
    END
  END NN4END[5]
  PIN NN4END[6]
    DIRECTION INPUT ;
    USE SIGNAL ;
    ANTENNAGATEAREA 0.159000 ;
    PORT
      LAYER met2 ;
        RECT 80.130 0.000 80.410 0.280 ;
    END
  END NN4END[6]
  PIN NN4END[7]
    DIRECTION INPUT ;
    USE SIGNAL ;
    ANTENNAGATEAREA 0.159000 ;
    PORT
      LAYER met2 ;
        RECT 81.510 0.000 81.790 0.280 ;
    END
  END NN4END[7]
  PIN NN4END[8]
    DIRECTION INPUT ;
    USE SIGNAL ;
    ANTENNAGATEAREA 0.159000 ;
    PORT
      LAYER met2 ;
        RECT 82.890 0.000 83.170 0.280 ;
    END
  END NN4END[8]
  PIN NN4END[9]
    DIRECTION INPUT ;
    USE SIGNAL ;
    ANTENNAGATEAREA 0.159000 ;
    PORT
      LAYER met2 ;
        RECT 84.270 0.000 84.550 0.280 ;
    END
  END NN4END[9]
  PIN N_GBUF_BEG[0]
    DIRECTION OUTPUT ;
    USE SIGNAL ;
    ANTENNADIFFAREA 0.702900 ;
    PORT
      LAYER met2 ;
        RECT 16.650 222.760 16.930 223.040 ;
    END
  END N_GBUF_BEG[0]
  PIN N_GBUF_BEG[1]
    DIRECTION OUTPUT ;
    USE SIGNAL ;
    ANTENNADIFFAREA 0.702900 ;
    PORT
      LAYER met2 ;
        RECT 18.030 222.760 18.310 223.040 ;
    END
  END N_GBUF_BEG[1]
  PIN N_GBUF_BEG[2]
    DIRECTION OUTPUT ;
    USE SIGNAL ;
    ANTENNADIFFAREA 0.702900 ;
    PORT
      LAYER met2 ;
        RECT 19.410 222.760 19.690 223.040 ;
    END
  END N_GBUF_BEG[2]
  PIN N_GBUF_BEG[3]
    DIRECTION OUTPUT ;
    USE SIGNAL ;
    ANTENNADIFFAREA 0.702900 ;
    PORT
      LAYER met2 ;
        RECT 20.790 222.760 21.070 223.040 ;
    END
  END N_GBUF_BEG[3]
  PIN N_GBUF_END[0]
    DIRECTION INPUT ;
    USE SIGNAL ;
    ANTENNAGATEAREA 2.308800 ;
    ANTENNADIFFAREA 1.738800 ;
    PORT
      LAYER met2 ;
        RECT 16.650 0.000 16.930 0.280 ;
    END
  END N_GBUF_END[0]
  PIN N_GBUF_END[1]
    DIRECTION INPUT ;
    USE SIGNAL ;
    ANTENNAGATEAREA 2.308800 ;
    ANTENNADIFFAREA 1.738800 ;
    PORT
      LAYER met2 ;
        RECT 18.030 0.000 18.310 0.280 ;
    END
  END N_GBUF_END[1]
  PIN N_GBUF_END[2]
    DIRECTION INPUT ;
    USE SIGNAL ;
    ANTENNAGATEAREA 0.813000 ;
    PORT
      LAYER met2 ;
        RECT 19.410 0.000 19.690 0.280 ;
    END
  END N_GBUF_END[2]
  PIN N_GBUF_END[3]
    DIRECTION INPUT ;
    USE SIGNAL ;
    ANTENNAGATEAREA 1.308000 ;
    PORT
      LAYER met2 ;
        RECT 20.790 0.000 21.070 0.280 ;
    END
  END N_GBUF_END[3]
  PIN S1BEG[0]
    DIRECTION OUTPUT ;
    USE SIGNAL ;
    ANTENNADIFFAREA 0.702900 ;
    PORT
      LAYER met2 ;
        RECT 95.310 0.000 95.590 0.280 ;
    END
  END S1BEG[0]
  PIN S1BEG[1]
    DIRECTION OUTPUT ;
    USE SIGNAL ;
    ANTENNADIFFAREA 0.702900 ;
    PORT
      LAYER met2 ;
        RECT 96.690 0.000 96.970 0.280 ;
    END
  END S1BEG[1]
  PIN S1BEG[2]
    DIRECTION OUTPUT ;
    USE SIGNAL ;
    ANTENNADIFFAREA 0.702900 ;
    PORT
      LAYER met2 ;
        RECT 98.070 0.000 98.350 0.280 ;
    END
  END S1BEG[2]
  PIN S1BEG[3]
    DIRECTION OUTPUT ;
    USE SIGNAL ;
    ANTENNADIFFAREA 0.702900 ;
    PORT
      LAYER met2 ;
        RECT 99.450 0.000 99.730 0.280 ;
    END
  END S1BEG[3]
  PIN S1END[0]
    DIRECTION INPUT ;
    USE SIGNAL ;
    ANTENNAGATEAREA 2.108400 ;
    ANTENNADIFFAREA 0.869400 ;
    PORT
      LAYER met2 ;
        RECT 95.310 222.760 95.590 223.040 ;
    END
  END S1END[0]
  PIN S1END[1]
    DIRECTION INPUT ;
    USE SIGNAL ;
    ANTENNAGATEAREA 1.272000 ;
    PORT
      LAYER met2 ;
        RECT 96.690 222.760 96.970 223.040 ;
    END
  END S1END[1]
  PIN S1END[2]
    DIRECTION INPUT ;
    USE SIGNAL ;
    ANTENNAGATEAREA 2.894100 ;
    ANTENNADIFFAREA 1.304100 ;
    PORT
      LAYER met2 ;
        RECT 98.070 222.760 98.350 223.040 ;
    END
  END S1END[2]
  PIN S1END[3]
    DIRECTION INPUT ;
    USE SIGNAL ;
    ANTENNAGATEAREA 1.590000 ;
    PORT
      LAYER met2 ;
        RECT 99.450 222.760 99.730 223.040 ;
    END
  END S1END[3]
  PIN S2BEG[0]
    DIRECTION OUTPUT ;
    USE SIGNAL ;
    ANTENNADIFFAREA 0.702900 ;
    PORT
      LAYER met2 ;
        RECT 100.830 0.000 101.110 0.280 ;
    END
  END S2BEG[0]
  PIN S2BEG[1]
    DIRECTION OUTPUT ;
    USE SIGNAL ;
    ANTENNADIFFAREA 0.702900 ;
    PORT
      LAYER met2 ;
        RECT 102.210 0.000 102.490 0.280 ;
    END
  END S2BEG[1]
  PIN S2BEG[2]
    DIRECTION OUTPUT ;
    USE SIGNAL ;
    ANTENNADIFFAREA 0.702900 ;
    PORT
      LAYER met2 ;
        RECT 103.590 0.000 103.870 0.280 ;
    END
  END S2BEG[2]
  PIN S2BEG[3]
    DIRECTION OUTPUT ;
    USE SIGNAL ;
    ANTENNADIFFAREA 0.702900 ;
    PORT
      LAYER met2 ;
        RECT 104.970 0.000 105.250 0.280 ;
    END
  END S2BEG[3]
  PIN S2BEG[4]
    DIRECTION OUTPUT ;
    USE SIGNAL ;
    ANTENNADIFFAREA 0.702900 ;
    PORT
      LAYER met2 ;
        RECT 106.350 0.000 106.630 0.280 ;
    END
  END S2BEG[4]
  PIN S2BEG[5]
    DIRECTION OUTPUT ;
    USE SIGNAL ;
    ANTENNADIFFAREA 0.702900 ;
    PORT
      LAYER met2 ;
        RECT 107.730 0.000 108.010 0.280 ;
    END
  END S2BEG[5]
  PIN S2BEG[6]
    DIRECTION OUTPUT ;
    USE SIGNAL ;
    ANTENNADIFFAREA 0.702900 ;
    PORT
      LAYER met2 ;
        RECT 109.110 0.000 109.390 0.280 ;
    END
  END S2BEG[6]
  PIN S2BEG[7]
    DIRECTION OUTPUT ;
    USE SIGNAL ;
    ANTENNADIFFAREA 0.702900 ;
    PORT
      LAYER met2 ;
        RECT 110.490 0.000 110.770 0.280 ;
    END
  END S2BEG[7]
  PIN S2BEGb[0]
    DIRECTION OUTPUT ;
    USE SIGNAL ;
    ANTENNADIFFAREA 0.702900 ;
    PORT
      LAYER met2 ;
        RECT 111.870 0.000 112.150 0.280 ;
    END
  END S2BEGb[0]
  PIN S2BEGb[1]
    DIRECTION OUTPUT ;
    USE SIGNAL ;
    ANTENNADIFFAREA 0.702900 ;
    PORT
      LAYER met2 ;
        RECT 113.250 0.000 113.530 0.280 ;
    END
  END S2BEGb[1]
  PIN S2BEGb[2]
    DIRECTION OUTPUT ;
    USE SIGNAL ;
    ANTENNADIFFAREA 0.702900 ;
    PORT
      LAYER met2 ;
        RECT 114.630 0.000 114.910 0.280 ;
    END
  END S2BEGb[2]
  PIN S2BEGb[3]
    DIRECTION OUTPUT ;
    USE SIGNAL ;
    ANTENNADIFFAREA 0.702900 ;
    PORT
      LAYER met2 ;
        RECT 116.010 0.000 116.290 0.280 ;
    END
  END S2BEGb[3]
  PIN S2BEGb[4]
    DIRECTION OUTPUT ;
    USE SIGNAL ;
    ANTENNADIFFAREA 0.702900 ;
    PORT
      LAYER met2 ;
        RECT 117.390 0.000 117.670 0.280 ;
    END
  END S2BEGb[4]
  PIN S2BEGb[5]
    DIRECTION OUTPUT ;
    USE SIGNAL ;
    ANTENNADIFFAREA 0.702900 ;
    PORT
      LAYER met2 ;
        RECT 118.770 0.000 119.050 0.280 ;
    END
  END S2BEGb[5]
  PIN S2BEGb[6]
    DIRECTION OUTPUT ;
    USE SIGNAL ;
    ANTENNADIFFAREA 0.702900 ;
    PORT
      LAYER met2 ;
        RECT 120.150 0.000 120.430 0.280 ;
    END
  END S2BEGb[6]
  PIN S2BEGb[7]
    DIRECTION OUTPUT ;
    USE SIGNAL ;
    ANTENNADIFFAREA 0.702900 ;
    PORT
      LAYER met2 ;
        RECT 121.530 0.000 121.810 0.280 ;
    END
  END S2BEGb[7]
  PIN S2END[0]
    DIRECTION INPUT ;
    USE SIGNAL ;
    ANTENNAGATEAREA 1.823400 ;
    ANTENNADIFFAREA 0.869400 ;
    PORT
      LAYER met2 ;
        RECT 111.870 222.760 112.150 223.040 ;
    END
  END S2END[0]
  PIN S2END[1]
    DIRECTION INPUT ;
    USE SIGNAL ;
    ANTENNAGATEAREA 0.954000 ;
    PORT
      LAYER met2 ;
        RECT 113.250 222.760 113.530 223.040 ;
    END
  END S2END[1]
  PIN S2END[2]
    DIRECTION INPUT ;
    USE SIGNAL ;
    ANTENNAGATEAREA 0.954000 ;
    PORT
      LAYER met2 ;
        RECT 114.630 222.760 114.910 223.040 ;
    END
  END S2END[2]
  PIN S2END[3]
    DIRECTION INPUT ;
    USE SIGNAL ;
    ANTENNAGATEAREA 1.229700 ;
    ANTENNADIFFAREA 0.434700 ;
    PORT
      LAYER met2 ;
        RECT 116.010 222.760 116.290 223.040 ;
    END
  END S2END[3]
  PIN S2END[4]
    DIRECTION INPUT ;
    USE SIGNAL ;
    ANTENNAGATEAREA 1.229700 ;
    ANTENNADIFFAREA 0.434700 ;
    PORT
      LAYER met2 ;
        RECT 117.390 222.760 117.670 223.040 ;
    END
  END S2END[4]
  PIN S2END[5]
    DIRECTION INPUT ;
    USE SIGNAL ;
    ANTENNAGATEAREA 2.968500 ;
    ANTENNADIFFAREA 2.173500 ;
    PORT
      LAYER met2 ;
        RECT 118.770 222.760 119.050 223.040 ;
    END
  END S2END[5]
  PIN S2END[6]
    DIRECTION INPUT ;
    USE SIGNAL ;
    ANTENNAGATEAREA 0.795000 ;
    PORT
      LAYER met2 ;
        RECT 120.150 222.760 120.430 223.040 ;
    END
  END S2END[6]
  PIN S2END[7]
    DIRECTION INPUT ;
    USE SIGNAL ;
    ANTENNAGATEAREA 0.954000 ;
    PORT
      LAYER met2 ;
        RECT 121.530 222.760 121.810 223.040 ;
    END
  END S2END[7]
  PIN S2MID[0]
    DIRECTION INPUT ;
    USE SIGNAL ;
    ANTENNAGATEAREA 2.374800 ;
    ANTENNADIFFAREA 1.738800 ;
    PORT
      LAYER met2 ;
        RECT 100.830 222.760 101.110 223.040 ;
    END
  END S2MID[0]
  PIN S2MID[1]
    DIRECTION INPUT ;
    USE SIGNAL ;
    ANTENNAGATEAREA 0.795000 ;
    PORT
      LAYER met2 ;
        RECT 102.210 222.760 102.490 223.040 ;
    END
  END S2MID[1]
  PIN S2MID[2]
    DIRECTION INPUT ;
    USE SIGNAL ;
    ANTENNAGATEAREA 0.636000 ;
    PORT
      LAYER met2 ;
        RECT 103.590 222.760 103.870 223.040 ;
    END
  END S2MID[2]
  PIN S2MID[3]
    DIRECTION INPUT ;
    USE SIGNAL ;
    ANTENNAGATEAREA 1.229700 ;
    ANTENNADIFFAREA 0.434700 ;
    PORT
      LAYER met2 ;
        RECT 104.970 222.760 105.250 223.040 ;
    END
  END S2MID[3]
  PIN S2MID[4]
    DIRECTION INPUT ;
    USE SIGNAL ;
    ANTENNAGATEAREA 0.972000 ;
    PORT
      LAYER met2 ;
        RECT 106.350 222.760 106.630 223.040 ;
    END
  END S2MID[4]
  PIN S2MID[5]
    DIRECTION INPUT ;
    USE SIGNAL ;
    ANTENNAGATEAREA 0.795000 ;
    PORT
      LAYER met2 ;
        RECT 107.730 222.760 108.010 223.040 ;
    END
  END S2MID[5]
  PIN S2MID[6]
    DIRECTION INPUT ;
    USE SIGNAL ;
    ANTENNAGATEAREA 0.636000 ;
    PORT
      LAYER met2 ;
        RECT 109.110 222.760 109.390 223.040 ;
    END
  END S2MID[6]
  PIN S2MID[7]
    DIRECTION INPUT ;
    USE SIGNAL ;
    ANTENNAGATEAREA 0.795000 ;
    PORT
      LAYER met2 ;
        RECT 110.490 222.760 110.770 223.040 ;
    END
  END S2MID[7]
  PIN S4BEG[0]
    DIRECTION OUTPUT ;
    USE SIGNAL ;
    ANTENNADIFFAREA 0.702900 ;
    PORT
      LAYER met2 ;
        RECT 122.910 0.000 123.190 0.280 ;
    END
  END S4BEG[0]
  PIN S4BEG[10]
    DIRECTION OUTPUT ;
    USE SIGNAL ;
    ANTENNADIFFAREA 0.702900 ;
    PORT
      LAYER met2 ;
        RECT 136.710 0.000 136.990 0.280 ;
    END
  END S4BEG[10]
  PIN S4BEG[11]
    DIRECTION OUTPUT ;
    USE SIGNAL ;
    ANTENNADIFFAREA 0.702900 ;
    PORT
      LAYER met2 ;
        RECT 138.090 0.000 138.370 0.280 ;
    END
  END S4BEG[11]
  PIN S4BEG[12]
    DIRECTION OUTPUT ;
    USE SIGNAL ;
    ANTENNADIFFAREA 0.702900 ;
    PORT
      LAYER met2 ;
        RECT 139.470 0.000 139.750 0.280 ;
    END
  END S4BEG[12]
  PIN S4BEG[13]
    DIRECTION OUTPUT ;
    USE SIGNAL ;
    ANTENNADIFFAREA 0.702900 ;
    PORT
      LAYER met2 ;
        RECT 140.850 0.000 141.130 0.280 ;
    END
  END S4BEG[13]
  PIN S4BEG[14]
    DIRECTION OUTPUT ;
    USE SIGNAL ;
    ANTENNADIFFAREA 0.702900 ;
    PORT
      LAYER met2 ;
        RECT 142.230 0.000 142.510 0.280 ;
    END
  END S4BEG[14]
  PIN S4BEG[15]
    DIRECTION OUTPUT ;
    USE SIGNAL ;
    ANTENNADIFFAREA 0.702900 ;
    PORT
      LAYER met2 ;
        RECT 143.610 0.000 143.890 0.280 ;
    END
  END S4BEG[15]
  PIN S4BEG[1]
    DIRECTION OUTPUT ;
    USE SIGNAL ;
    ANTENNADIFFAREA 0.702900 ;
    PORT
      LAYER met2 ;
        RECT 124.290 0.000 124.570 0.280 ;
    END
  END S4BEG[1]
  PIN S4BEG[2]
    DIRECTION OUTPUT ;
    USE SIGNAL ;
    ANTENNADIFFAREA 0.702900 ;
    PORT
      LAYER met2 ;
        RECT 125.670 0.000 125.950 0.280 ;
    END
  END S4BEG[2]
  PIN S4BEG[3]
    DIRECTION OUTPUT ;
    USE SIGNAL ;
    ANTENNADIFFAREA 0.702900 ;
    PORT
      LAYER met2 ;
        RECT 127.050 0.000 127.330 0.280 ;
    END
  END S4BEG[3]
  PIN S4BEG[4]
    DIRECTION OUTPUT ;
    USE SIGNAL ;
    ANTENNADIFFAREA 0.702900 ;
    PORT
      LAYER met2 ;
        RECT 128.430 0.000 128.710 0.280 ;
    END
  END S4BEG[4]
  PIN S4BEG[5]
    DIRECTION OUTPUT ;
    USE SIGNAL ;
    ANTENNADIFFAREA 0.702900 ;
    PORT
      LAYER met2 ;
        RECT 129.810 0.000 130.090 0.280 ;
    END
  END S4BEG[5]
  PIN S4BEG[6]
    DIRECTION OUTPUT ;
    USE SIGNAL ;
    ANTENNADIFFAREA 0.702900 ;
    PORT
      LAYER met2 ;
        RECT 131.190 0.000 131.470 0.280 ;
    END
  END S4BEG[6]
  PIN S4BEG[7]
    DIRECTION OUTPUT ;
    USE SIGNAL ;
    ANTENNADIFFAREA 0.702900 ;
    PORT
      LAYER met2 ;
        RECT 132.570 0.000 132.850 0.280 ;
    END
  END S4BEG[7]
  PIN S4BEG[8]
    DIRECTION OUTPUT ;
    USE SIGNAL ;
    ANTENNADIFFAREA 0.702900 ;
    PORT
      LAYER met2 ;
        RECT 133.950 0.000 134.230 0.280 ;
    END
  END S4BEG[8]
  PIN S4BEG[9]
    DIRECTION OUTPUT ;
    USE SIGNAL ;
    ANTENNADIFFAREA 0.702900 ;
    PORT
      LAYER met2 ;
        RECT 135.330 0.000 135.610 0.280 ;
    END
  END S4BEG[9]
  PIN S4END[0]
    DIRECTION INPUT ;
    USE SIGNAL ;
    ANTENNAGATEAREA 1.229700 ;
    ANTENNADIFFAREA 0.434700 ;
    PORT
      LAYER met2 ;
        RECT 122.910 222.760 123.190 223.040 ;
    END
  END S4END[0]
  PIN S4END[10]
    DIRECTION INPUT ;
    USE SIGNAL ;
    ANTENNAGATEAREA 0.159000 ;
    PORT
      LAYER met2 ;
        RECT 136.710 222.760 136.990 223.040 ;
    END
  END S4END[10]
  PIN S4END[11]
    DIRECTION INPUT ;
    USE SIGNAL ;
    ANTENNAGATEAREA 0.159000 ;
    PORT
      LAYER met2 ;
        RECT 138.090 222.760 138.370 223.040 ;
    END
  END S4END[11]
  PIN S4END[12]
    DIRECTION INPUT ;
    USE SIGNAL ;
    ANTENNAGATEAREA 0.159000 ;
    PORT
      LAYER met2 ;
        RECT 139.470 222.760 139.750 223.040 ;
    END
  END S4END[12]
  PIN S4END[13]
    DIRECTION INPUT ;
    USE SIGNAL ;
    ANTENNAGATEAREA 0.159000 ;
    PORT
      LAYER met2 ;
        RECT 140.850 222.760 141.130 223.040 ;
    END
  END S4END[13]
  PIN S4END[14]
    DIRECTION INPUT ;
    USE SIGNAL ;
    ANTENNAGATEAREA 0.159000 ;
    PORT
      LAYER met2 ;
        RECT 142.230 222.760 142.510 223.040 ;
    END
  END S4END[14]
  PIN S4END[15]
    DIRECTION INPUT ;
    USE SIGNAL ;
    ANTENNAGATEAREA 0.159000 ;
    PORT
      LAYER met2 ;
        RECT 143.610 222.760 143.890 223.040 ;
    END
  END S4END[15]
  PIN S4END[1]
    DIRECTION INPUT ;
    USE SIGNAL ;
    ANTENNAGATEAREA 1.229700 ;
    ANTENNADIFFAREA 0.434700 ;
    PORT
      LAYER met2 ;
        RECT 124.290 222.760 124.570 223.040 ;
    END
  END S4END[1]
  PIN S4END[2]
    DIRECTION INPUT ;
    USE SIGNAL ;
    ANTENNAGATEAREA 2.968500 ;
    ANTENNADIFFAREA 2.173500 ;
    PORT
      LAYER met2 ;
        RECT 125.670 222.760 125.950 223.040 ;
    END
  END S4END[2]
  PIN S4END[3]
    DIRECTION INPUT ;
    USE SIGNAL ;
    ANTENNAGATEAREA 1.664400 ;
    ANTENNADIFFAREA 0.869400 ;
    PORT
      LAYER met2 ;
        RECT 127.050 222.760 127.330 223.040 ;
    END
  END S4END[3]
  PIN S4END[4]
    DIRECTION INPUT ;
    USE SIGNAL ;
    ANTENNAGATEAREA 0.159000 ;
    PORT
      LAYER met2 ;
        RECT 128.430 222.760 128.710 223.040 ;
    END
  END S4END[4]
  PIN S4END[5]
    DIRECTION INPUT ;
    USE SIGNAL ;
    ANTENNAGATEAREA 0.159000 ;
    PORT
      LAYER met2 ;
        RECT 129.810 222.760 130.090 223.040 ;
    END
  END S4END[5]
  PIN S4END[6]
    DIRECTION INPUT ;
    USE SIGNAL ;
    ANTENNAGATEAREA 0.159000 ;
    PORT
      LAYER met2 ;
        RECT 131.190 222.760 131.470 223.040 ;
    END
  END S4END[6]
  PIN S4END[7]
    DIRECTION INPUT ;
    USE SIGNAL ;
    ANTENNAGATEAREA 0.159000 ;
    PORT
      LAYER met2 ;
        RECT 132.570 222.760 132.850 223.040 ;
    END
  END S4END[7]
  PIN S4END[8]
    DIRECTION INPUT ;
    USE SIGNAL ;
    ANTENNAGATEAREA 0.159000 ;
    PORT
      LAYER met2 ;
        RECT 133.950 222.760 134.230 223.040 ;
    END
  END S4END[8]
  PIN S4END[9]
    DIRECTION INPUT ;
    USE SIGNAL ;
    ANTENNAGATEAREA 0.159000 ;
    PORT
      LAYER met2 ;
        RECT 135.330 222.760 135.610 223.040 ;
    END
  END S4END[9]
  PIN SS4BEG[0]
    DIRECTION OUTPUT ;
    USE SIGNAL ;
    ANTENNADIFFAREA 0.702900 ;
    PORT
      LAYER met2 ;
        RECT 144.990 0.000 145.270 0.280 ;
    END
  END SS4BEG[0]
  PIN SS4BEG[10]
    DIRECTION OUTPUT ;
    USE SIGNAL ;
    ANTENNADIFFAREA 0.702900 ;
    PORT
      LAYER met2 ;
        RECT 158.790 0.000 159.070 0.280 ;
    END
  END SS4BEG[10]
  PIN SS4BEG[11]
    DIRECTION OUTPUT ;
    USE SIGNAL ;
    ANTENNADIFFAREA 0.702900 ;
    PORT
      LAYER met2 ;
        RECT 160.170 0.000 160.450 0.280 ;
    END
  END SS4BEG[11]
  PIN SS4BEG[12]
    DIRECTION OUTPUT ;
    USE SIGNAL ;
    ANTENNADIFFAREA 0.702900 ;
    PORT
      LAYER met2 ;
        RECT 161.550 0.000 161.830 0.280 ;
    END
  END SS4BEG[12]
  PIN SS4BEG[13]
    DIRECTION OUTPUT ;
    USE SIGNAL ;
    ANTENNADIFFAREA 0.702900 ;
    PORT
      LAYER met2 ;
        RECT 162.930 0.000 163.210 0.280 ;
    END
  END SS4BEG[13]
  PIN SS4BEG[14]
    DIRECTION OUTPUT ;
    USE SIGNAL ;
    ANTENNADIFFAREA 0.702900 ;
    PORT
      LAYER met2 ;
        RECT 164.310 0.000 164.590 0.280 ;
    END
  END SS4BEG[14]
  PIN SS4BEG[15]
    DIRECTION OUTPUT ;
    USE SIGNAL ;
    ANTENNADIFFAREA 0.702900 ;
    PORT
      LAYER met2 ;
        RECT 165.690 0.000 165.970 0.280 ;
    END
  END SS4BEG[15]
  PIN SS4BEG[1]
    DIRECTION OUTPUT ;
    USE SIGNAL ;
    ANTENNADIFFAREA 0.702900 ;
    PORT
      LAYER met2 ;
        RECT 146.370 0.000 146.650 0.280 ;
    END
  END SS4BEG[1]
  PIN SS4BEG[2]
    DIRECTION OUTPUT ;
    USE SIGNAL ;
    ANTENNADIFFAREA 0.702900 ;
    PORT
      LAYER met2 ;
        RECT 147.750 0.000 148.030 0.280 ;
    END
  END SS4BEG[2]
  PIN SS4BEG[3]
    DIRECTION OUTPUT ;
    USE SIGNAL ;
    ANTENNADIFFAREA 0.702900 ;
    PORT
      LAYER met2 ;
        RECT 149.130 0.000 149.410 0.280 ;
    END
  END SS4BEG[3]
  PIN SS4BEG[4]
    DIRECTION OUTPUT ;
    USE SIGNAL ;
    ANTENNADIFFAREA 0.702900 ;
    PORT
      LAYER met2 ;
        RECT 150.510 0.000 150.790 0.280 ;
    END
  END SS4BEG[4]
  PIN SS4BEG[5]
    DIRECTION OUTPUT ;
    USE SIGNAL ;
    ANTENNADIFFAREA 0.702900 ;
    PORT
      LAYER met2 ;
        RECT 151.890 0.000 152.170 0.280 ;
    END
  END SS4BEG[5]
  PIN SS4BEG[6]
    DIRECTION OUTPUT ;
    USE SIGNAL ;
    ANTENNADIFFAREA 0.702900 ;
    PORT
      LAYER met2 ;
        RECT 153.270 0.000 153.550 0.280 ;
    END
  END SS4BEG[6]
  PIN SS4BEG[7]
    DIRECTION OUTPUT ;
    USE SIGNAL ;
    ANTENNADIFFAREA 0.702900 ;
    PORT
      LAYER met2 ;
        RECT 154.650 0.000 154.930 0.280 ;
    END
  END SS4BEG[7]
  PIN SS4BEG[8]
    DIRECTION OUTPUT ;
    USE SIGNAL ;
    ANTENNADIFFAREA 0.702900 ;
    PORT
      LAYER met2 ;
        RECT 156.030 0.000 156.310 0.280 ;
    END
  END SS4BEG[8]
  PIN SS4BEG[9]
    DIRECTION OUTPUT ;
    USE SIGNAL ;
    ANTENNADIFFAREA 0.702900 ;
    PORT
      LAYER met2 ;
        RECT 157.410 0.000 157.690 0.280 ;
    END
  END SS4BEG[9]
  PIN SS4END[0]
    DIRECTION INPUT ;
    USE SIGNAL ;
    ANTENNAGATEAREA 0.477000 ;
    PORT
      LAYER met2 ;
        RECT 144.990 222.760 145.270 223.040 ;
    END
  END SS4END[0]
  PIN SS4END[10]
    DIRECTION INPUT ;
    USE SIGNAL ;
    ANTENNAGATEAREA 0.159000 ;
    PORT
      LAYER met2 ;
        RECT 158.790 222.760 159.070 223.040 ;
    END
  END SS4END[10]
  PIN SS4END[11]
    DIRECTION INPUT ;
    USE SIGNAL ;
    ANTENNAGATEAREA 0.159000 ;
    PORT
      LAYER met2 ;
        RECT 160.170 222.760 160.450 223.040 ;
    END
  END SS4END[11]
  PIN SS4END[12]
    DIRECTION INPUT ;
    USE SIGNAL ;
    ANTENNAGATEAREA 0.159000 ;
    PORT
      LAYER met2 ;
        RECT 161.550 222.760 161.830 223.040 ;
    END
  END SS4END[12]
  PIN SS4END[13]
    DIRECTION INPUT ;
    USE SIGNAL ;
    ANTENNAGATEAREA 0.159000 ;
    PORT
      LAYER met2 ;
        RECT 162.930 222.760 163.210 223.040 ;
    END
  END SS4END[13]
  PIN SS4END[14]
    DIRECTION INPUT ;
    USE SIGNAL ;
    ANTENNAGATEAREA 0.159000 ;
    PORT
      LAYER met2 ;
        RECT 164.310 222.760 164.590 223.040 ;
    END
  END SS4END[14]
  PIN SS4END[15]
    DIRECTION INPUT ;
    USE SIGNAL ;
    ANTENNAGATEAREA 0.159000 ;
    PORT
      LAYER met2 ;
        RECT 165.690 222.760 165.970 223.040 ;
    END
  END SS4END[15]
  PIN SS4END[1]
    DIRECTION INPUT ;
    USE SIGNAL ;
    ANTENNAGATEAREA 1.781100 ;
    ANTENNADIFFAREA 1.304100 ;
    PORT
      LAYER met2 ;
        RECT 146.370 222.760 146.650 223.040 ;
    END
  END SS4END[1]
  PIN SS4END[2]
    DIRECTION INPUT ;
    USE SIGNAL ;
    ANTENNAGATEAREA 0.911700 ;
    ANTENNADIFFAREA 0.434700 ;
    PORT
      LAYER met2 ;
        RECT 147.750 222.760 148.030 223.040 ;
    END
  END SS4END[2]
  PIN SS4END[3]
    DIRECTION INPUT ;
    USE SIGNAL ;
    ANTENNAGATEAREA 1.781100 ;
    ANTENNADIFFAREA 1.304100 ;
    PORT
      LAYER met2 ;
        RECT 149.130 222.760 149.410 223.040 ;
    END
  END SS4END[3]
  PIN SS4END[4]
    DIRECTION INPUT ;
    USE SIGNAL ;
    ANTENNAGATEAREA 0.159000 ;
    PORT
      LAYER met2 ;
        RECT 150.510 222.760 150.790 223.040 ;
    END
  END SS4END[4]
  PIN SS4END[5]
    DIRECTION INPUT ;
    USE SIGNAL ;
    ANTENNAGATEAREA 0.159000 ;
    PORT
      LAYER met2 ;
        RECT 151.890 222.760 152.170 223.040 ;
    END
  END SS4END[5]
  PIN SS4END[6]
    DIRECTION INPUT ;
    USE SIGNAL ;
    ANTENNAGATEAREA 0.159000 ;
    PORT
      LAYER met2 ;
        RECT 153.270 222.760 153.550 223.040 ;
    END
  END SS4END[6]
  PIN SS4END[7]
    DIRECTION INPUT ;
    USE SIGNAL ;
    ANTENNAGATEAREA 0.159000 ;
    PORT
      LAYER met2 ;
        RECT 154.650 222.760 154.930 223.040 ;
    END
  END SS4END[7]
  PIN SS4END[8]
    DIRECTION INPUT ;
    USE SIGNAL ;
    ANTENNAGATEAREA 0.159000 ;
    PORT
      LAYER met2 ;
        RECT 156.030 222.760 156.310 223.040 ;
    END
  END SS4END[8]
  PIN SS4END[9]
    DIRECTION INPUT ;
    USE SIGNAL ;
    ANTENNAGATEAREA 0.159000 ;
    PORT
      LAYER met2 ;
        RECT 157.410 222.760 157.690 223.040 ;
    END
  END SS4END[9]
  PIN VGND
    DIRECTION INOUT ;
    USE GROUND ;
    PORT
      LAYER met4 ;
        RECT 12.260 0.000 13.860 223.040 ;
    END
    PORT
      LAYER met4 ;
        RECT 42.260 0.000 43.860 223.040 ;
    END
    PORT
      LAYER met4 ;
        RECT 72.260 0.000 73.860 223.040 ;
    END
    PORT
      LAYER met4 ;
        RECT 102.260 0.000 103.860 223.040 ;
    END
    PORT
      LAYER met4 ;
        RECT 132.260 0.000 133.860 223.040 ;
    END
    PORT
      LAYER met4 ;
        RECT 162.260 0.000 163.860 223.040 ;
    END
    PORT
      LAYER met4 ;
        RECT 192.260 0.000 193.860 223.040 ;
    END
  END VGND
  PIN VPWR
    DIRECTION INOUT ;
    USE POWER ;
    PORT
      LAYER met4 ;
        RECT 6.960 0.000 8.560 223.040 ;
    END
    PORT
      LAYER met4 ;
        RECT 36.960 0.000 38.560 223.040 ;
    END
    PORT
      LAYER met4 ;
        RECT 66.960 0.000 68.560 223.040 ;
    END
    PORT
      LAYER met4 ;
        RECT 96.960 0.000 98.560 223.040 ;
    END
    PORT
      LAYER met4 ;
        RECT 126.960 0.000 128.560 223.040 ;
    END
    PORT
      LAYER met4 ;
        RECT 156.960 0.000 158.560 223.040 ;
    END
    PORT
      LAYER met4 ;
        RECT 186.960 0.000 188.560 223.040 ;
    END
  END VPWR
  PIN W1BEG[0]
    DIRECTION OUTPUT ;
    USE SIGNAL ;
    ANTENNADIFFAREA 0.702900 ;
    PORT
      LAYER met3 ;
        RECT 0.000 24.520 0.600 25.120 ;
    END
  END W1BEG[0]
  PIN W1BEG[1]
    DIRECTION OUTPUT ;
    USE SIGNAL ;
    ANTENNADIFFAREA 0.702900 ;
    PORT
      LAYER met3 ;
        RECT 0.000 25.880 0.600 26.480 ;
    END
  END W1BEG[1]
  PIN W1BEG[2]
    DIRECTION OUTPUT ;
    USE SIGNAL ;
    ANTENNADIFFAREA 0.702900 ;
    PORT
      LAYER met3 ;
        RECT 0.000 27.240 0.600 27.840 ;
    END
  END W1BEG[2]
  PIN W1BEG[3]
    DIRECTION OUTPUT ;
    USE SIGNAL ;
    ANTENNADIFFAREA 0.702900 ;
    PORT
      LAYER met3 ;
        RECT 0.000 28.600 0.600 29.200 ;
    END
  END W1BEG[3]
  PIN W1END[0]
    DIRECTION INPUT ;
    USE SIGNAL ;
    ANTENNAGATEAREA 1.239000 ;
    PORT
      LAYER met3 ;
        RECT 210.080 24.520 210.680 25.120 ;
    END
  END W1END[0]
  PIN W1END[1]
    DIRECTION INPUT ;
    USE SIGNAL ;
    ANTENNAGATEAREA 1.431000 ;
    PORT
      LAYER met3 ;
        RECT 210.080 25.880 210.680 26.480 ;
    END
  END W1END[1]
  PIN W1END[2]
    DIRECTION INPUT ;
    USE SIGNAL ;
    ANTENNAGATEAREA 1.749000 ;
    PORT
      LAYER met3 ;
        RECT 210.080 27.240 210.680 27.840 ;
    END
  END W1END[2]
  PIN W1END[3]
    DIRECTION INPUT ;
    USE SIGNAL ;
    ANTENNAGATEAREA 1.749000 ;
    PORT
      LAYER met3 ;
        RECT 210.080 28.600 210.680 29.200 ;
    END
  END W1END[3]
  PIN W2BEG[0]
    DIRECTION OUTPUT ;
    USE SIGNAL ;
    ANTENNADIFFAREA 0.702900 ;
    PORT
      LAYER met3 ;
        RECT 0.000 29.960 0.600 30.560 ;
    END
  END W2BEG[0]
  PIN W2BEG[1]
    DIRECTION OUTPUT ;
    USE SIGNAL ;
    ANTENNADIFFAREA 0.702900 ;
    PORT
      LAYER met3 ;
        RECT 0.000 31.320 0.600 31.920 ;
    END
  END W2BEG[1]
  PIN W2BEG[2]
    DIRECTION OUTPUT ;
    USE SIGNAL ;
    ANTENNADIFFAREA 0.702900 ;
    PORT
      LAYER met3 ;
        RECT 0.000 32.680 0.600 33.280 ;
    END
  END W2BEG[2]
  PIN W2BEG[3]
    DIRECTION OUTPUT ;
    USE SIGNAL ;
    ANTENNADIFFAREA 0.702900 ;
    PORT
      LAYER met3 ;
        RECT 0.000 34.040 0.600 34.640 ;
    END
  END W2BEG[3]
  PIN W2BEG[4]
    DIRECTION OUTPUT ;
    USE SIGNAL ;
    ANTENNADIFFAREA 0.702900 ;
    PORT
      LAYER met3 ;
        RECT 0.000 35.400 0.600 36.000 ;
    END
  END W2BEG[4]
  PIN W2BEG[5]
    DIRECTION OUTPUT ;
    USE SIGNAL ;
    ANTENNADIFFAREA 0.702900 ;
    PORT
      LAYER met3 ;
        RECT 0.000 36.760 0.600 37.360 ;
    END
  END W2BEG[5]
  PIN W2BEG[6]
    DIRECTION OUTPUT ;
    USE SIGNAL ;
    ANTENNADIFFAREA 0.702900 ;
    PORT
      LAYER met3 ;
        RECT 0.000 38.120 0.600 38.720 ;
    END
  END W2BEG[6]
  PIN W2BEG[7]
    DIRECTION OUTPUT ;
    USE SIGNAL ;
    ANTENNADIFFAREA 0.702900 ;
    PORT
      LAYER met3 ;
        RECT 0.000 39.480 0.600 40.080 ;
    END
  END W2BEG[7]
  PIN W2BEGb[0]
    DIRECTION OUTPUT ;
    USE SIGNAL ;
    ANTENNADIFFAREA 0.702900 ;
    PORT
      LAYER met3 ;
        RECT 0.000 40.840 0.600 41.440 ;
    END
  END W2BEGb[0]
  PIN W2BEGb[1]
    DIRECTION OUTPUT ;
    USE SIGNAL ;
    ANTENNADIFFAREA 0.702900 ;
    PORT
      LAYER met3 ;
        RECT 0.000 42.200 0.600 42.800 ;
    END
  END W2BEGb[1]
  PIN W2BEGb[2]
    DIRECTION OUTPUT ;
    USE SIGNAL ;
    ANTENNADIFFAREA 0.702900 ;
    PORT
      LAYER met3 ;
        RECT 0.000 43.560 0.600 44.160 ;
    END
  END W2BEGb[2]
  PIN W2BEGb[3]
    DIRECTION OUTPUT ;
    USE SIGNAL ;
    ANTENNADIFFAREA 0.702900 ;
    PORT
      LAYER met3 ;
        RECT 0.000 44.920 0.600 45.520 ;
    END
  END W2BEGb[3]
  PIN W2BEGb[4]
    DIRECTION OUTPUT ;
    USE SIGNAL ;
    ANTENNADIFFAREA 0.702900 ;
    PORT
      LAYER met3 ;
        RECT 0.000 46.280 0.600 46.880 ;
    END
  END W2BEGb[4]
  PIN W2BEGb[5]
    DIRECTION OUTPUT ;
    USE SIGNAL ;
    ANTENNADIFFAREA 0.702900 ;
    PORT
      LAYER met3 ;
        RECT 0.000 47.640 0.600 48.240 ;
    END
  END W2BEGb[5]
  PIN W2BEGb[6]
    DIRECTION OUTPUT ;
    USE SIGNAL ;
    ANTENNADIFFAREA 0.702900 ;
    PORT
      LAYER met3 ;
        RECT 0.000 49.000 0.600 49.600 ;
    END
  END W2BEGb[6]
  PIN W2BEGb[7]
    DIRECTION OUTPUT ;
    USE SIGNAL ;
    ANTENNADIFFAREA 0.702900 ;
    PORT
      LAYER met3 ;
        RECT 0.000 50.360 0.600 50.960 ;
    END
  END W2BEGb[7]
  PIN W2END[0]
    DIRECTION INPUT ;
    USE SIGNAL ;
    ANTENNAGATEAREA 0.954000 ;
    PORT
      LAYER met3 ;
        RECT 210.080 40.840 210.680 41.440 ;
    END
  END W2END[0]
  PIN W2END[1]
    DIRECTION INPUT ;
    USE SIGNAL ;
    ANTENNAGATEAREA 1.388700 ;
    ANTENNADIFFAREA 0.434700 ;
    PORT
      LAYER met3 ;
        RECT 210.080 42.200 210.680 42.800 ;
    END
  END W2END[1]
  PIN W2END[2]
    DIRECTION INPUT ;
    USE SIGNAL ;
    ANTENNAGATEAREA 0.954000 ;
    PORT
      LAYER met3 ;
        RECT 210.080 43.560 210.680 44.160 ;
    END
  END W2END[2]
  PIN W2END[3]
    DIRECTION INPUT ;
    USE SIGNAL ;
    ANTENNAGATEAREA 2.258100 ;
    ANTENNADIFFAREA 1.304100 ;
    PORT
      LAYER met3 ;
        RECT 210.080 44.920 210.680 45.520 ;
    END
  END W2END[3]
  PIN W2END[4]
    DIRECTION INPUT ;
    USE SIGNAL ;
    ANTENNAGATEAREA 1.113000 ;
    PORT
      LAYER met3 ;
        RECT 210.080 46.280 210.680 46.880 ;
    END
  END W2END[4]
  PIN W2END[5]
    DIRECTION INPUT ;
    USE SIGNAL ;
    ANTENNAGATEAREA 0.954000 ;
    PORT
      LAYER met3 ;
        RECT 210.080 47.640 210.680 48.240 ;
    END
  END W2END[5]
  PIN W2END[6]
    DIRECTION INPUT ;
    USE SIGNAL ;
    ANTENNAGATEAREA 0.954000 ;
    PORT
      LAYER met3 ;
        RECT 210.080 49.000 210.680 49.600 ;
    END
  END W2END[6]
  PIN W2END[7]
    DIRECTION INPUT ;
    USE SIGNAL ;
    ANTENNAGATEAREA 1.113000 ;
    PORT
      LAYER met3 ;
        RECT 210.080 50.360 210.680 50.960 ;
    END
  END W2END[7]
  PIN W2MID[0]
    DIRECTION INPUT ;
    USE SIGNAL ;
    ANTENNAGATEAREA 1.070700 ;
    ANTENNADIFFAREA 0.434700 ;
    PORT
      LAYER met3 ;
        RECT 210.080 29.960 210.680 30.560 ;
    END
  END W2MID[0]
  PIN W2MID[1]
    DIRECTION INPUT ;
    USE SIGNAL ;
    ANTENNAGATEAREA 1.229700 ;
    ANTENNADIFFAREA 0.434700 ;
    PORT
      LAYER met3 ;
        RECT 210.080 31.320 210.680 31.920 ;
    END
  END W2MID[1]
  PIN W2MID[2]
    DIRECTION INPUT ;
    USE SIGNAL ;
    ANTENNAGATEAREA 2.374800 ;
    ANTENNADIFFAREA 1.738800 ;
    PORT
      LAYER met3 ;
        RECT 210.080 32.680 210.680 33.280 ;
    END
  END W2MID[2]
  PIN W2MID[3]
    DIRECTION INPUT ;
    USE SIGNAL ;
    ANTENNAGATEAREA 0.795000 ;
    PORT
      LAYER met3 ;
        RECT 210.080 34.040 210.680 34.640 ;
    END
  END W2MID[3]
  PIN W2MID[4]
    DIRECTION INPUT ;
    USE SIGNAL ;
    ANTENNAGATEAREA 1.098000 ;
    PORT
      LAYER met3 ;
        RECT 210.080 35.400 210.680 36.000 ;
    END
  END W2MID[4]
  PIN W2MID[5]
    DIRECTION INPUT ;
    USE SIGNAL ;
    ANTENNAGATEAREA 1.229700 ;
    ANTENNADIFFAREA 0.434700 ;
    PORT
      LAYER met3 ;
        RECT 210.080 36.760 210.680 37.360 ;
    END
  END W2MID[5]
  PIN W2MID[6]
    DIRECTION INPUT ;
    USE SIGNAL ;
    ANTENNAGATEAREA 1.070700 ;
    ANTENNADIFFAREA 0.434700 ;
    PORT
      LAYER met3 ;
        RECT 210.080 38.120 210.680 38.720 ;
    END
  END W2MID[6]
  PIN W2MID[7]
    DIRECTION INPUT ;
    USE SIGNAL ;
    ANTENNAGATEAREA 1.229700 ;
    ANTENNADIFFAREA 0.434700 ;
    PORT
      LAYER met3 ;
        RECT 210.080 39.480 210.680 40.080 ;
    END
  END W2MID[7]
  PIN W6BEG[0]
    DIRECTION OUTPUT ;
    USE SIGNAL ;
    ANTENNADIFFAREA 0.702900 ;
    PORT
      LAYER met3 ;
        RECT 0.000 73.480 0.600 74.080 ;
    END
  END W6BEG[0]
  PIN W6BEG[10]
    DIRECTION OUTPUT ;
    USE SIGNAL ;
    ANTENNADIFFAREA 0.702900 ;
    PORT
      LAYER met3 ;
        RECT 0.000 87.080 0.600 87.680 ;
    END
  END W6BEG[10]
  PIN W6BEG[11]
    DIRECTION OUTPUT ;
    USE SIGNAL ;
    ANTENNADIFFAREA 0.702900 ;
    PORT
      LAYER met3 ;
        RECT 0.000 88.440 0.600 89.040 ;
    END
  END W6BEG[11]
  PIN W6BEG[1]
    DIRECTION OUTPUT ;
    USE SIGNAL ;
    ANTENNADIFFAREA 0.702900 ;
    PORT
      LAYER met3 ;
        RECT 0.000 74.840 0.600 75.440 ;
    END
  END W6BEG[1]
  PIN W6BEG[2]
    DIRECTION OUTPUT ;
    USE SIGNAL ;
    ANTENNADIFFAREA 0.702900 ;
    PORT
      LAYER met3 ;
        RECT 0.000 76.200 0.600 76.800 ;
    END
  END W6BEG[2]
  PIN W6BEG[3]
    DIRECTION OUTPUT ;
    USE SIGNAL ;
    ANTENNADIFFAREA 0.702900 ;
    PORT
      LAYER met3 ;
        RECT 0.000 77.560 0.600 78.160 ;
    END
  END W6BEG[3]
  PIN W6BEG[4]
    DIRECTION OUTPUT ;
    USE SIGNAL ;
    ANTENNADIFFAREA 0.702900 ;
    PORT
      LAYER met3 ;
        RECT 0.000 78.920 0.600 79.520 ;
    END
  END W6BEG[4]
  PIN W6BEG[5]
    DIRECTION OUTPUT ;
    USE SIGNAL ;
    ANTENNADIFFAREA 0.702900 ;
    PORT
      LAYER met3 ;
        RECT 0.000 80.280 0.600 80.880 ;
    END
  END W6BEG[5]
  PIN W6BEG[6]
    DIRECTION OUTPUT ;
    USE SIGNAL ;
    ANTENNADIFFAREA 0.702900 ;
    PORT
      LAYER met3 ;
        RECT 0.000 81.640 0.600 82.240 ;
    END
  END W6BEG[6]
  PIN W6BEG[7]
    DIRECTION OUTPUT ;
    USE SIGNAL ;
    ANTENNADIFFAREA 0.702900 ;
    PORT
      LAYER met3 ;
        RECT 0.000 83.000 0.600 83.600 ;
    END
  END W6BEG[7]
  PIN W6BEG[8]
    DIRECTION OUTPUT ;
    USE SIGNAL ;
    ANTENNADIFFAREA 0.702900 ;
    PORT
      LAYER met3 ;
        RECT 0.000 84.360 0.600 84.960 ;
    END
  END W6BEG[8]
  PIN W6BEG[9]
    DIRECTION OUTPUT ;
    USE SIGNAL ;
    ANTENNADIFFAREA 0.702900 ;
    PORT
      LAYER met3 ;
        RECT 0.000 85.720 0.600 86.320 ;
    END
  END W6BEG[9]
  PIN W6END[0]
    DIRECTION INPUT ;
    USE SIGNAL ;
    ANTENNAGATEAREA 1.706700 ;
    ANTENNADIFFAREA 0.434700 ;
    PORT
      LAYER met3 ;
        RECT 210.080 73.480 210.680 74.080 ;
    END
  END W6END[0]
  PIN W6END[10]
    DIRECTION INPUT ;
    USE SIGNAL ;
    ANTENNAGATEAREA 0.159000 ;
    PORT
      LAYER met3 ;
        RECT 210.080 87.080 210.680 87.680 ;
    END
  END W6END[10]
  PIN W6END[11]
    DIRECTION INPUT ;
    USE SIGNAL ;
    ANTENNAGATEAREA 0.159000 ;
    PORT
      LAYER met3 ;
        RECT 210.080 88.440 210.680 89.040 ;
    END
  END W6END[11]
  PIN W6END[1]
    DIRECTION INPUT ;
    USE SIGNAL ;
    ANTENNAGATEAREA 3.763500 ;
    ANTENNADIFFAREA 2.173500 ;
    PORT
      LAYER met3 ;
        RECT 210.080 74.840 210.680 75.440 ;
    END
  END W6END[1]
  PIN W6END[2]
    DIRECTION INPUT ;
    USE SIGNAL ;
    ANTENNAGATEAREA 0.159000 ;
    PORT
      LAYER met3 ;
        RECT 210.080 76.200 210.680 76.800 ;
    END
  END W6END[2]
  PIN W6END[3]
    DIRECTION INPUT ;
    USE SIGNAL ;
    ANTENNAGATEAREA 0.159000 ;
    PORT
      LAYER met3 ;
        RECT 210.080 77.560 210.680 78.160 ;
    END
  END W6END[3]
  PIN W6END[4]
    DIRECTION INPUT ;
    USE SIGNAL ;
    ANTENNAGATEAREA 0.159000 ;
    PORT
      LAYER met3 ;
        RECT 210.080 78.920 210.680 79.520 ;
    END
  END W6END[4]
  PIN W6END[5]
    DIRECTION INPUT ;
    USE SIGNAL ;
    ANTENNAGATEAREA 0.159000 ;
    PORT
      LAYER met3 ;
        RECT 210.080 80.280 210.680 80.880 ;
    END
  END W6END[5]
  PIN W6END[6]
    DIRECTION INPUT ;
    USE SIGNAL ;
    ANTENNAGATEAREA 0.159000 ;
    PORT
      LAYER met3 ;
        RECT 210.080 81.640 210.680 82.240 ;
    END
  END W6END[6]
  PIN W6END[7]
    DIRECTION INPUT ;
    USE SIGNAL ;
    ANTENNAGATEAREA 0.159000 ;
    PORT
      LAYER met3 ;
        RECT 210.080 83.000 210.680 83.600 ;
    END
  END W6END[7]
  PIN W6END[8]
    DIRECTION INPUT ;
    USE SIGNAL ;
    ANTENNAGATEAREA 0.159000 ;
    PORT
      LAYER met3 ;
        RECT 210.080 84.360 210.680 84.960 ;
    END
  END W6END[8]
  PIN W6END[9]
    DIRECTION INPUT ;
    USE SIGNAL ;
    ANTENNAGATEAREA 0.159000 ;
    PORT
      LAYER met3 ;
        RECT 210.080 85.720 210.680 86.320 ;
    END
  END W6END[9]
  PIN WW4BEG[0]
    DIRECTION OUTPUT ;
    USE SIGNAL ;
    ANTENNADIFFAREA 0.702900 ;
    PORT
      LAYER met3 ;
        RECT 0.000 51.720 0.600 52.320 ;
    END
  END WW4BEG[0]
  PIN WW4BEG[10]
    DIRECTION OUTPUT ;
    USE SIGNAL ;
    ANTENNADIFFAREA 0.702900 ;
    PORT
      LAYER met3 ;
        RECT 0.000 65.320 0.600 65.920 ;
    END
  END WW4BEG[10]
  PIN WW4BEG[11]
    DIRECTION OUTPUT ;
    USE SIGNAL ;
    ANTENNADIFFAREA 0.702900 ;
    PORT
      LAYER met3 ;
        RECT 0.000 66.680 0.600 67.280 ;
    END
  END WW4BEG[11]
  PIN WW4BEG[12]
    DIRECTION OUTPUT ;
    USE SIGNAL ;
    ANTENNADIFFAREA 0.702900 ;
    PORT
      LAYER met3 ;
        RECT 0.000 68.040 0.600 68.640 ;
    END
  END WW4BEG[12]
  PIN WW4BEG[13]
    DIRECTION OUTPUT ;
    USE SIGNAL ;
    ANTENNADIFFAREA 0.702900 ;
    PORT
      LAYER met3 ;
        RECT 0.000 69.400 0.600 70.000 ;
    END
  END WW4BEG[13]
  PIN WW4BEG[14]
    DIRECTION OUTPUT ;
    USE SIGNAL ;
    ANTENNADIFFAREA 0.702900 ;
    PORT
      LAYER met3 ;
        RECT 0.000 70.760 0.600 71.360 ;
    END
  END WW4BEG[14]
  PIN WW4BEG[15]
    DIRECTION OUTPUT ;
    USE SIGNAL ;
    ANTENNADIFFAREA 0.702900 ;
    PORT
      LAYER met3 ;
        RECT 0.000 72.120 0.600 72.720 ;
    END
  END WW4BEG[15]
  PIN WW4BEG[1]
    DIRECTION OUTPUT ;
    USE SIGNAL ;
    ANTENNADIFFAREA 0.702900 ;
    PORT
      LAYER met3 ;
        RECT 0.000 53.080 0.600 53.680 ;
    END
  END WW4BEG[1]
  PIN WW4BEG[2]
    DIRECTION OUTPUT ;
    USE SIGNAL ;
    ANTENNADIFFAREA 0.702900 ;
    PORT
      LAYER met3 ;
        RECT 0.000 54.440 0.600 55.040 ;
    END
  END WW4BEG[2]
  PIN WW4BEG[3]
    DIRECTION OUTPUT ;
    USE SIGNAL ;
    ANTENNADIFFAREA 0.702900 ;
    PORT
      LAYER met3 ;
        RECT 0.000 55.800 0.600 56.400 ;
    END
  END WW4BEG[3]
  PIN WW4BEG[4]
    DIRECTION OUTPUT ;
    USE SIGNAL ;
    ANTENNADIFFAREA 0.702900 ;
    PORT
      LAYER met3 ;
        RECT 0.000 57.160 0.600 57.760 ;
    END
  END WW4BEG[4]
  PIN WW4BEG[5]
    DIRECTION OUTPUT ;
    USE SIGNAL ;
    ANTENNADIFFAREA 0.702900 ;
    PORT
      LAYER met3 ;
        RECT 0.000 58.520 0.600 59.120 ;
    END
  END WW4BEG[5]
  PIN WW4BEG[6]
    DIRECTION OUTPUT ;
    USE SIGNAL ;
    ANTENNADIFFAREA 0.702900 ;
    PORT
      LAYER met3 ;
        RECT 0.000 59.880 0.600 60.480 ;
    END
  END WW4BEG[6]
  PIN WW4BEG[7]
    DIRECTION OUTPUT ;
    USE SIGNAL ;
    ANTENNADIFFAREA 0.702900 ;
    PORT
      LAYER met3 ;
        RECT 0.000 61.240 0.600 61.840 ;
    END
  END WW4BEG[7]
  PIN WW4BEG[8]
    DIRECTION OUTPUT ;
    USE SIGNAL ;
    ANTENNADIFFAREA 0.702900 ;
    PORT
      LAYER met3 ;
        RECT 0.000 62.600 0.600 63.200 ;
    END
  END WW4BEG[8]
  PIN WW4BEG[9]
    DIRECTION OUTPUT ;
    USE SIGNAL ;
    ANTENNADIFFAREA 0.702900 ;
    PORT
      LAYER met3 ;
        RECT 0.000 63.960 0.600 64.560 ;
    END
  END WW4BEG[9]
  PIN WW4END[0]
    DIRECTION INPUT ;
    USE SIGNAL ;
    ANTENNAGATEAREA 0.477000 ;
    PORT
      LAYER met3 ;
        RECT 210.080 51.720 210.680 52.320 ;
    END
  END WW4END[0]
  PIN WW4END[10]
    DIRECTION INPUT ;
    USE SIGNAL ;
    ANTENNAGATEAREA 0.159000 ;
    PORT
      LAYER met3 ;
        RECT 210.080 65.320 210.680 65.920 ;
    END
  END WW4END[10]
  PIN WW4END[11]
    DIRECTION INPUT ;
    USE SIGNAL ;
    ANTENNAGATEAREA 0.159000 ;
    PORT
      LAYER met3 ;
        RECT 210.080 66.680 210.680 67.280 ;
    END
  END WW4END[11]
  PIN WW4END[12]
    DIRECTION INPUT ;
    USE SIGNAL ;
    ANTENNAGATEAREA 0.159000 ;
    PORT
      LAYER met3 ;
        RECT 210.080 68.040 210.680 68.640 ;
    END
  END WW4END[12]
  PIN WW4END[13]
    DIRECTION INPUT ;
    USE SIGNAL ;
    ANTENNAGATEAREA 0.159000 ;
    PORT
      LAYER met3 ;
        RECT 210.080 69.400 210.680 70.000 ;
    END
  END WW4END[13]
  PIN WW4END[14]
    DIRECTION INPUT ;
    USE SIGNAL ;
    ANTENNAGATEAREA 0.159000 ;
    PORT
      LAYER met3 ;
        RECT 210.080 70.760 210.680 71.360 ;
    END
  END WW4END[14]
  PIN WW4END[15]
    DIRECTION INPUT ;
    USE SIGNAL ;
    ANTENNAGATEAREA 0.159000 ;
    PORT
      LAYER met3 ;
        RECT 210.080 72.120 210.680 72.720 ;
    END
  END WW4END[15]
  PIN WW4END[1]
    DIRECTION INPUT ;
    USE SIGNAL ;
    ANTENNAGATEAREA 1.781100 ;
    ANTENNADIFFAREA 1.304100 ;
    PORT
      LAYER met3 ;
        RECT 210.080 53.080 210.680 53.680 ;
    END
  END WW4END[1]
  PIN WW4END[2]
    DIRECTION INPUT ;
    USE SIGNAL ;
    ANTENNAGATEAREA 1.940100 ;
    ANTENNADIFFAREA 1.304100 ;
    PORT
      LAYER met3 ;
        RECT 210.080 54.440 210.680 55.040 ;
    END
  END WW4END[2]
  PIN WW4END[3]
    DIRECTION INPUT ;
    USE SIGNAL ;
    ANTENNAGATEAREA 0.477000 ;
    PORT
      LAYER met3 ;
        RECT 210.080 55.800 210.680 56.400 ;
    END
  END WW4END[3]
  PIN WW4END[4]
    DIRECTION INPUT ;
    USE SIGNAL ;
    ANTENNAGATEAREA 0.159000 ;
    PORT
      LAYER met3 ;
        RECT 210.080 57.160 210.680 57.760 ;
    END
  END WW4END[4]
  PIN WW4END[5]
    DIRECTION INPUT ;
    USE SIGNAL ;
    ANTENNAGATEAREA 0.159000 ;
    PORT
      LAYER met3 ;
        RECT 210.080 58.520 210.680 59.120 ;
    END
  END WW4END[5]
  PIN WW4END[6]
    DIRECTION INPUT ;
    USE SIGNAL ;
    ANTENNAGATEAREA 0.159000 ;
    PORT
      LAYER met3 ;
        RECT 210.080 59.880 210.680 60.480 ;
    END
  END WW4END[6]
  PIN WW4END[7]
    DIRECTION INPUT ;
    USE SIGNAL ;
    ANTENNAGATEAREA 0.159000 ;
    PORT
      LAYER met3 ;
        RECT 210.080 61.240 210.680 61.840 ;
    END
  END WW4END[7]
  PIN WW4END[8]
    DIRECTION INPUT ;
    USE SIGNAL ;
    ANTENNAGATEAREA 0.159000 ;
    PORT
      LAYER met3 ;
        RECT 210.080 62.600 210.680 63.200 ;
    END
  END WW4END[8]
  PIN WW4END[9]
    DIRECTION INPUT ;
    USE SIGNAL ;
    ANTENNAGATEAREA 0.159000 ;
    PORT
      LAYER met3 ;
        RECT 210.080 63.960 210.680 64.560 ;
    END
  END WW4END[9]
  OBS
      LAYER nwell ;
        RECT 2.570 2.635 208.110 220.405 ;
      LAYER li1 ;
        RECT 2.760 2.635 207.920 220.405 ;
      LAYER met1 ;
        RECT 0.530 0.380 209.690 221.980 ;
      LAYER met2 ;
        RECT 0.550 222.480 16.370 222.770 ;
        RECT 17.210 222.480 17.750 222.770 ;
        RECT 18.590 222.480 19.130 222.770 ;
        RECT 19.970 222.480 20.510 222.770 ;
        RECT 21.350 222.480 21.890 222.770 ;
        RECT 22.730 222.480 23.270 222.770 ;
        RECT 24.110 222.480 24.650 222.770 ;
        RECT 25.490 222.480 26.030 222.770 ;
        RECT 26.870 222.480 27.410 222.770 ;
        RECT 28.250 222.480 28.790 222.770 ;
        RECT 29.630 222.480 30.170 222.770 ;
        RECT 31.010 222.480 31.550 222.770 ;
        RECT 32.390 222.480 32.930 222.770 ;
        RECT 33.770 222.480 34.310 222.770 ;
        RECT 35.150 222.480 35.690 222.770 ;
        RECT 36.530 222.480 37.070 222.770 ;
        RECT 37.910 222.480 38.450 222.770 ;
        RECT 39.290 222.480 39.830 222.770 ;
        RECT 40.670 222.480 41.210 222.770 ;
        RECT 42.050 222.480 42.590 222.770 ;
        RECT 43.430 222.480 43.970 222.770 ;
        RECT 44.810 222.480 45.350 222.770 ;
        RECT 46.190 222.480 46.730 222.770 ;
        RECT 47.570 222.480 48.110 222.770 ;
        RECT 48.950 222.480 49.490 222.770 ;
        RECT 50.330 222.480 50.870 222.770 ;
        RECT 51.710 222.480 52.250 222.770 ;
        RECT 53.090 222.480 53.630 222.770 ;
        RECT 54.470 222.480 55.010 222.770 ;
        RECT 55.850 222.480 56.390 222.770 ;
        RECT 57.230 222.480 57.770 222.770 ;
        RECT 58.610 222.480 59.150 222.770 ;
        RECT 59.990 222.480 60.530 222.770 ;
        RECT 61.370 222.480 61.910 222.770 ;
        RECT 62.750 222.480 63.290 222.770 ;
        RECT 64.130 222.480 64.670 222.770 ;
        RECT 65.510 222.480 66.050 222.770 ;
        RECT 66.890 222.480 67.430 222.770 ;
        RECT 68.270 222.480 68.810 222.770 ;
        RECT 69.650 222.480 70.190 222.770 ;
        RECT 71.030 222.480 71.570 222.770 ;
        RECT 72.410 222.480 72.950 222.770 ;
        RECT 73.790 222.480 74.330 222.770 ;
        RECT 75.170 222.480 75.710 222.770 ;
        RECT 76.550 222.480 77.090 222.770 ;
        RECT 77.930 222.480 78.470 222.770 ;
        RECT 79.310 222.480 79.850 222.770 ;
        RECT 80.690 222.480 81.230 222.770 ;
        RECT 82.070 222.480 82.610 222.770 ;
        RECT 83.450 222.480 83.990 222.770 ;
        RECT 84.830 222.480 85.370 222.770 ;
        RECT 86.210 222.480 86.750 222.770 ;
        RECT 87.590 222.480 88.130 222.770 ;
        RECT 88.970 222.480 89.510 222.770 ;
        RECT 90.350 222.480 90.890 222.770 ;
        RECT 91.730 222.480 92.270 222.770 ;
        RECT 93.110 222.480 93.650 222.770 ;
        RECT 94.490 222.480 95.030 222.770 ;
        RECT 95.870 222.480 96.410 222.770 ;
        RECT 97.250 222.480 97.790 222.770 ;
        RECT 98.630 222.480 99.170 222.770 ;
        RECT 100.010 222.480 100.550 222.770 ;
        RECT 101.390 222.480 101.930 222.770 ;
        RECT 102.770 222.480 103.310 222.770 ;
        RECT 104.150 222.480 104.690 222.770 ;
        RECT 105.530 222.480 106.070 222.770 ;
        RECT 106.910 222.480 107.450 222.770 ;
        RECT 108.290 222.480 108.830 222.770 ;
        RECT 109.670 222.480 110.210 222.770 ;
        RECT 111.050 222.480 111.590 222.770 ;
        RECT 112.430 222.480 112.970 222.770 ;
        RECT 113.810 222.480 114.350 222.770 ;
        RECT 115.190 222.480 115.730 222.770 ;
        RECT 116.570 222.480 117.110 222.770 ;
        RECT 117.950 222.480 118.490 222.770 ;
        RECT 119.330 222.480 119.870 222.770 ;
        RECT 120.710 222.480 121.250 222.770 ;
        RECT 122.090 222.480 122.630 222.770 ;
        RECT 123.470 222.480 124.010 222.770 ;
        RECT 124.850 222.480 125.390 222.770 ;
        RECT 126.230 222.480 126.770 222.770 ;
        RECT 127.610 222.480 128.150 222.770 ;
        RECT 128.990 222.480 129.530 222.770 ;
        RECT 130.370 222.480 130.910 222.770 ;
        RECT 131.750 222.480 132.290 222.770 ;
        RECT 133.130 222.480 133.670 222.770 ;
        RECT 134.510 222.480 135.050 222.770 ;
        RECT 135.890 222.480 136.430 222.770 ;
        RECT 137.270 222.480 137.810 222.770 ;
        RECT 138.650 222.480 139.190 222.770 ;
        RECT 140.030 222.480 140.570 222.770 ;
        RECT 141.410 222.480 141.950 222.770 ;
        RECT 142.790 222.480 143.330 222.770 ;
        RECT 144.170 222.480 144.710 222.770 ;
        RECT 145.550 222.480 146.090 222.770 ;
        RECT 146.930 222.480 147.470 222.770 ;
        RECT 148.310 222.480 148.850 222.770 ;
        RECT 149.690 222.480 150.230 222.770 ;
        RECT 151.070 222.480 151.610 222.770 ;
        RECT 152.450 222.480 152.990 222.770 ;
        RECT 153.830 222.480 154.370 222.770 ;
        RECT 155.210 222.480 155.750 222.770 ;
        RECT 156.590 222.480 157.130 222.770 ;
        RECT 157.970 222.480 158.510 222.770 ;
        RECT 159.350 222.480 159.890 222.770 ;
        RECT 160.730 222.480 161.270 222.770 ;
        RECT 162.110 222.480 162.650 222.770 ;
        RECT 163.490 222.480 164.030 222.770 ;
        RECT 164.870 222.480 165.410 222.770 ;
        RECT 166.250 222.480 166.790 222.770 ;
        RECT 167.630 222.480 168.170 222.770 ;
        RECT 169.010 222.480 169.550 222.770 ;
        RECT 170.390 222.480 170.930 222.770 ;
        RECT 171.770 222.480 172.310 222.770 ;
        RECT 173.150 222.480 173.690 222.770 ;
        RECT 174.530 222.480 175.070 222.770 ;
        RECT 175.910 222.480 176.450 222.770 ;
        RECT 177.290 222.480 177.830 222.770 ;
        RECT 178.670 222.480 179.210 222.770 ;
        RECT 180.050 222.480 180.590 222.770 ;
        RECT 181.430 222.480 181.970 222.770 ;
        RECT 182.810 222.480 183.350 222.770 ;
        RECT 184.190 222.480 184.730 222.770 ;
        RECT 185.570 222.480 186.110 222.770 ;
        RECT 186.950 222.480 187.490 222.770 ;
        RECT 188.330 222.480 188.870 222.770 ;
        RECT 189.710 222.480 190.250 222.770 ;
        RECT 191.090 222.480 191.630 222.770 ;
        RECT 192.470 222.480 193.010 222.770 ;
        RECT 193.850 222.480 209.670 222.770 ;
        RECT 0.550 0.560 209.670 222.480 ;
        RECT 0.550 0.270 16.370 0.560 ;
        RECT 17.210 0.270 17.750 0.560 ;
        RECT 18.590 0.270 19.130 0.560 ;
        RECT 19.970 0.270 20.510 0.560 ;
        RECT 21.350 0.270 21.890 0.560 ;
        RECT 22.730 0.270 23.270 0.560 ;
        RECT 24.110 0.270 24.650 0.560 ;
        RECT 25.490 0.270 26.030 0.560 ;
        RECT 26.870 0.270 27.410 0.560 ;
        RECT 28.250 0.270 28.790 0.560 ;
        RECT 29.630 0.270 30.170 0.560 ;
        RECT 31.010 0.270 31.550 0.560 ;
        RECT 32.390 0.270 32.930 0.560 ;
        RECT 33.770 0.270 34.310 0.560 ;
        RECT 35.150 0.270 35.690 0.560 ;
        RECT 36.530 0.270 37.070 0.560 ;
        RECT 37.910 0.270 38.450 0.560 ;
        RECT 39.290 0.270 39.830 0.560 ;
        RECT 40.670 0.270 41.210 0.560 ;
        RECT 42.050 0.270 42.590 0.560 ;
        RECT 43.430 0.270 43.970 0.560 ;
        RECT 44.810 0.270 45.350 0.560 ;
        RECT 46.190 0.270 46.730 0.560 ;
        RECT 47.570 0.270 48.110 0.560 ;
        RECT 48.950 0.270 49.490 0.560 ;
        RECT 50.330 0.270 50.870 0.560 ;
        RECT 51.710 0.270 52.250 0.560 ;
        RECT 53.090 0.270 53.630 0.560 ;
        RECT 54.470 0.270 55.010 0.560 ;
        RECT 55.850 0.270 56.390 0.560 ;
        RECT 57.230 0.270 57.770 0.560 ;
        RECT 58.610 0.270 59.150 0.560 ;
        RECT 59.990 0.270 60.530 0.560 ;
        RECT 61.370 0.270 61.910 0.560 ;
        RECT 62.750 0.270 63.290 0.560 ;
        RECT 64.130 0.270 64.670 0.560 ;
        RECT 65.510 0.270 66.050 0.560 ;
        RECT 66.890 0.270 67.430 0.560 ;
        RECT 68.270 0.270 68.810 0.560 ;
        RECT 69.650 0.270 70.190 0.560 ;
        RECT 71.030 0.270 71.570 0.560 ;
        RECT 72.410 0.270 72.950 0.560 ;
        RECT 73.790 0.270 74.330 0.560 ;
        RECT 75.170 0.270 75.710 0.560 ;
        RECT 76.550 0.270 77.090 0.560 ;
        RECT 77.930 0.270 78.470 0.560 ;
        RECT 79.310 0.270 79.850 0.560 ;
        RECT 80.690 0.270 81.230 0.560 ;
        RECT 82.070 0.270 82.610 0.560 ;
        RECT 83.450 0.270 83.990 0.560 ;
        RECT 84.830 0.270 85.370 0.560 ;
        RECT 86.210 0.270 86.750 0.560 ;
        RECT 87.590 0.270 88.130 0.560 ;
        RECT 88.970 0.270 89.510 0.560 ;
        RECT 90.350 0.270 90.890 0.560 ;
        RECT 91.730 0.270 92.270 0.560 ;
        RECT 93.110 0.270 93.650 0.560 ;
        RECT 94.490 0.270 95.030 0.560 ;
        RECT 95.870 0.270 96.410 0.560 ;
        RECT 97.250 0.270 97.790 0.560 ;
        RECT 98.630 0.270 99.170 0.560 ;
        RECT 100.010 0.270 100.550 0.560 ;
        RECT 101.390 0.270 101.930 0.560 ;
        RECT 102.770 0.270 103.310 0.560 ;
        RECT 104.150 0.270 104.690 0.560 ;
        RECT 105.530 0.270 106.070 0.560 ;
        RECT 106.910 0.270 107.450 0.560 ;
        RECT 108.290 0.270 108.830 0.560 ;
        RECT 109.670 0.270 110.210 0.560 ;
        RECT 111.050 0.270 111.590 0.560 ;
        RECT 112.430 0.270 112.970 0.560 ;
        RECT 113.810 0.270 114.350 0.560 ;
        RECT 115.190 0.270 115.730 0.560 ;
        RECT 116.570 0.270 117.110 0.560 ;
        RECT 117.950 0.270 118.490 0.560 ;
        RECT 119.330 0.270 119.870 0.560 ;
        RECT 120.710 0.270 121.250 0.560 ;
        RECT 122.090 0.270 122.630 0.560 ;
        RECT 123.470 0.270 124.010 0.560 ;
        RECT 124.850 0.270 125.390 0.560 ;
        RECT 126.230 0.270 126.770 0.560 ;
        RECT 127.610 0.270 128.150 0.560 ;
        RECT 128.990 0.270 129.530 0.560 ;
        RECT 130.370 0.270 130.910 0.560 ;
        RECT 131.750 0.270 132.290 0.560 ;
        RECT 133.130 0.270 133.670 0.560 ;
        RECT 134.510 0.270 135.050 0.560 ;
        RECT 135.890 0.270 136.430 0.560 ;
        RECT 137.270 0.270 137.810 0.560 ;
        RECT 138.650 0.270 139.190 0.560 ;
        RECT 140.030 0.270 140.570 0.560 ;
        RECT 141.410 0.270 141.950 0.560 ;
        RECT 142.790 0.270 143.330 0.560 ;
        RECT 144.170 0.270 144.710 0.560 ;
        RECT 145.550 0.270 146.090 0.560 ;
        RECT 146.930 0.270 147.470 0.560 ;
        RECT 148.310 0.270 148.850 0.560 ;
        RECT 149.690 0.270 150.230 0.560 ;
        RECT 151.070 0.270 151.610 0.560 ;
        RECT 152.450 0.270 152.990 0.560 ;
        RECT 153.830 0.270 154.370 0.560 ;
        RECT 155.210 0.270 155.750 0.560 ;
        RECT 156.590 0.270 157.130 0.560 ;
        RECT 157.970 0.270 158.510 0.560 ;
        RECT 159.350 0.270 159.890 0.560 ;
        RECT 160.730 0.270 161.270 0.560 ;
        RECT 162.110 0.270 162.650 0.560 ;
        RECT 163.490 0.270 164.030 0.560 ;
        RECT 164.870 0.270 165.410 0.560 ;
        RECT 166.250 0.270 166.790 0.560 ;
        RECT 167.630 0.270 168.170 0.560 ;
        RECT 169.010 0.270 169.550 0.560 ;
        RECT 170.390 0.270 170.930 0.560 ;
        RECT 171.770 0.270 172.310 0.560 ;
        RECT 173.150 0.270 173.690 0.560 ;
        RECT 174.530 0.270 175.070 0.560 ;
        RECT 175.910 0.270 176.450 0.560 ;
        RECT 177.290 0.270 177.830 0.560 ;
        RECT 178.670 0.270 179.210 0.560 ;
        RECT 180.050 0.270 180.590 0.560 ;
        RECT 181.430 0.270 181.970 0.560 ;
        RECT 182.810 0.270 183.350 0.560 ;
        RECT 184.190 0.270 184.730 0.560 ;
        RECT 185.570 0.270 186.110 0.560 ;
        RECT 186.950 0.270 187.490 0.560 ;
        RECT 188.330 0.270 188.870 0.560 ;
        RECT 189.710 0.270 190.250 0.560 ;
        RECT 191.090 0.270 191.630 0.560 ;
        RECT 192.470 0.270 193.010 0.560 ;
        RECT 193.850 0.270 209.670 0.560 ;
      LAYER met3 ;
        RECT 0.600 198.240 210.080 222.185 ;
        RECT 1.000 24.120 209.680 198.240 ;
        RECT 0.600 0.855 210.080 24.120 ;
      LAYER met4 ;
        RECT 0.310 0.855 6.560 222.185 ;
        RECT 8.960 0.855 11.860 222.185 ;
        RECT 14.260 0.855 36.560 222.185 ;
        RECT 38.960 0.855 41.860 222.185 ;
        RECT 44.260 0.855 66.560 222.185 ;
        RECT 68.960 0.855 71.860 222.185 ;
        RECT 74.260 0.855 96.560 222.185 ;
        RECT 98.960 0.855 101.860 222.185 ;
        RECT 104.260 0.855 126.560 222.185 ;
        RECT 128.960 0.855 131.860 222.185 ;
        RECT 134.260 0.855 156.560 222.185 ;
        RECT 158.960 0.855 161.860 222.185 ;
        RECT 164.260 0.855 186.560 222.185 ;
        RECT 188.960 0.855 191.860 222.185 ;
        RECT 194.260 0.855 202.105 222.185 ;
  END
END LUT4x8_ha
END LIBRARY

